VERSION 5.7 ;
  NOWIREEXTENSIONATPIN ON ;
  DIVIDERCHAR "/" ;
  BUSBITCHARS "[]" ;
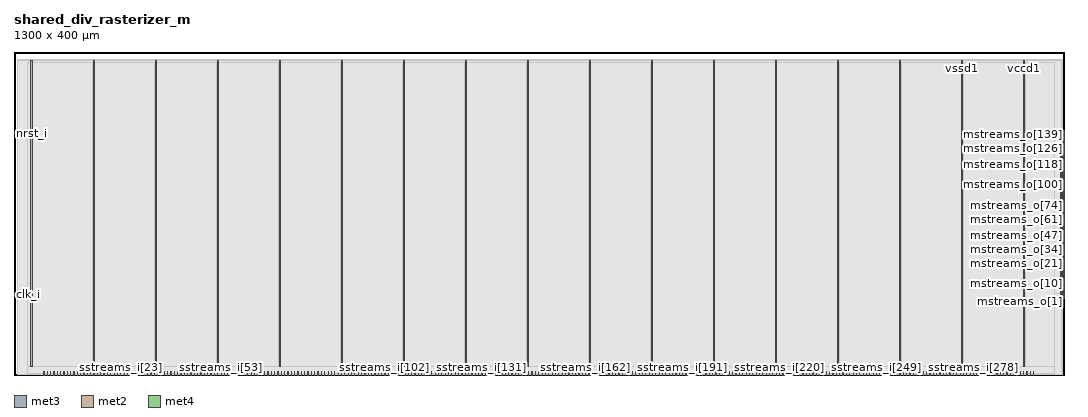
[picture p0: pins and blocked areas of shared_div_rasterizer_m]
MACRO shared_div_rasterizer_m
  CLASS BLOCK ;
  FOREIGN shared_div_rasterizer_m ;
  ORIGIN 0.000 0.000 ;
  SIZE 1300.000 BY 400.000 ;
  PIN clk_i
    DIRECTION INPUT ;
    USE SIGNAL ;
    ANTENNAGATEAREA 0.852000 ;
    ANTENNADIFFAREA 0.434700 ;
    PORT
      LAYER met3 ;
        RECT 0.000 99.320 4.000 99.920 ;
    END
  END clk_i
  PIN mstreams_i[0]
    DIRECTION INPUT ;
    USE SIGNAL ;
    ANTENNAGATEAREA 0.213000 ;
    PORT
      LAYER met3 ;
        RECT 1296.000 95.240 1300.000 95.840 ;
    END
  END mstreams_i[0]
  PIN mstreams_i[1]
    DIRECTION INPUT ;
    USE SIGNAL ;
    ANTENNAGATEAREA 0.159000 ;
    PORT
      LAYER met3 ;
        RECT 1296.000 96.600 1300.000 97.200 ;
    END
  END mstreams_i[1]
  PIN mstreams_i[2]
    DIRECTION INPUT ;
    USE SIGNAL ;
    ANTENNAGATEAREA 0.247500 ;
    PORT
      LAYER met3 ;
        RECT 1296.000 97.960 1300.000 98.560 ;
    END
  END mstreams_i[2]
  PIN mstreams_o[0]
    DIRECTION OUTPUT TRISTATE ;
    USE SIGNAL ;
    ANTENNADIFFAREA 2.673000 ;
    PORT
      LAYER met3 ;
        RECT 1296.000 99.320 1300.000 99.920 ;
    END
  END mstreams_o[0]
  PIN mstreams_o[100]
    DIRECTION OUTPUT TRISTATE ;
    USE SIGNAL ;
    ANTENNADIFFAREA 2.673000 ;
    PORT
      LAYER met3 ;
        RECT 1296.000 235.320 1300.000 235.920 ;
    END
  END mstreams_o[100]
  PIN mstreams_o[101]
    DIRECTION OUTPUT TRISTATE ;
    USE SIGNAL ;
    ANTENNADIFFAREA 2.673000 ;
    PORT
      LAYER met3 ;
        RECT 1296.000 236.680 1300.000 237.280 ;
    END
  END mstreams_o[101]
  PIN mstreams_o[102]
    DIRECTION OUTPUT TRISTATE ;
    USE SIGNAL ;
    ANTENNADIFFAREA 2.673000 ;
    PORT
      LAYER met3 ;
        RECT 1296.000 238.040 1300.000 238.640 ;
    END
  END mstreams_o[102]
  PIN mstreams_o[103]
    DIRECTION OUTPUT TRISTATE ;
    USE SIGNAL ;
    ANTENNADIFFAREA 2.673000 ;
    PORT
      LAYER met3 ;
        RECT 1296.000 239.400 1300.000 240.000 ;
    END
  END mstreams_o[103]
  PIN mstreams_o[104]
    DIRECTION OUTPUT TRISTATE ;
    USE SIGNAL ;
    ANTENNADIFFAREA 2.673000 ;
    PORT
      LAYER met3 ;
        RECT 1296.000 240.760 1300.000 241.360 ;
    END
  END mstreams_o[104]
  PIN mstreams_o[105]
    DIRECTION OUTPUT TRISTATE ;
    USE SIGNAL ;
    ANTENNADIFFAREA 2.673000 ;
    PORT
      LAYER met3 ;
        RECT 1296.000 242.120 1300.000 242.720 ;
    END
  END mstreams_o[105]
  PIN mstreams_o[106]
    DIRECTION OUTPUT TRISTATE ;
    USE SIGNAL ;
    ANTENNADIFFAREA 2.673000 ;
    PORT
      LAYER met3 ;
        RECT 1296.000 243.480 1300.000 244.080 ;
    END
  END mstreams_o[106]
  PIN mstreams_o[107]
    DIRECTION OUTPUT TRISTATE ;
    USE SIGNAL ;
    ANTENNADIFFAREA 2.673000 ;
    PORT
      LAYER met3 ;
        RECT 1296.000 244.840 1300.000 245.440 ;
    END
  END mstreams_o[107]
  PIN mstreams_o[108]
    DIRECTION OUTPUT TRISTATE ;
    USE SIGNAL ;
    ANTENNADIFFAREA 2.673000 ;
    PORT
      LAYER met3 ;
        RECT 1296.000 246.200 1300.000 246.800 ;
    END
  END mstreams_o[108]
  PIN mstreams_o[109]
    DIRECTION OUTPUT TRISTATE ;
    USE SIGNAL ;
    ANTENNADIFFAREA 2.673000 ;
    PORT
      LAYER met3 ;
        RECT 1296.000 247.560 1300.000 248.160 ;
    END
  END mstreams_o[109]
  PIN mstreams_o[10]
    DIRECTION OUTPUT TRISTATE ;
    USE SIGNAL ;
    ANTENNADIFFAREA 2.673000 ;
    PORT
      LAYER met3 ;
        RECT 1296.000 112.920 1300.000 113.520 ;
    END
  END mstreams_o[10]
  PIN mstreams_o[110]
    DIRECTION OUTPUT TRISTATE ;
    USE SIGNAL ;
    ANTENNADIFFAREA 2.673000 ;
    PORT
      LAYER met3 ;
        RECT 1296.000 248.920 1300.000 249.520 ;
    END
  END mstreams_o[110]
  PIN mstreams_o[111]
    DIRECTION OUTPUT TRISTATE ;
    USE SIGNAL ;
    ANTENNADIFFAREA 2.673000 ;
    PORT
      LAYER met3 ;
        RECT 1296.000 250.280 1300.000 250.880 ;
    END
  END mstreams_o[111]
  PIN mstreams_o[112]
    DIRECTION OUTPUT TRISTATE ;
    USE SIGNAL ;
    ANTENNADIFFAREA 2.673000 ;
    PORT
      LAYER met3 ;
        RECT 1296.000 251.640 1300.000 252.240 ;
    END
  END mstreams_o[112]
  PIN mstreams_o[113]
    DIRECTION OUTPUT TRISTATE ;
    USE SIGNAL ;
    ANTENNADIFFAREA 2.673000 ;
    PORT
      LAYER met3 ;
        RECT 1296.000 253.000 1300.000 253.600 ;
    END
  END mstreams_o[113]
  PIN mstreams_o[114]
    DIRECTION OUTPUT TRISTATE ;
    USE SIGNAL ;
    ANTENNADIFFAREA 2.673000 ;
    PORT
      LAYER met3 ;
        RECT 1296.000 254.360 1300.000 254.960 ;
    END
  END mstreams_o[114]
  PIN mstreams_o[115]
    DIRECTION OUTPUT TRISTATE ;
    USE SIGNAL ;
    ANTENNADIFFAREA 2.673000 ;
    PORT
      LAYER met3 ;
        RECT 1296.000 255.720 1300.000 256.320 ;
    END
  END mstreams_o[115]
  PIN mstreams_o[116]
    DIRECTION OUTPUT TRISTATE ;
    USE SIGNAL ;
    ANTENNADIFFAREA 2.673000 ;
    PORT
      LAYER met3 ;
        RECT 1296.000 257.080 1300.000 257.680 ;
    END
  END mstreams_o[116]
  PIN mstreams_o[117]
    DIRECTION OUTPUT TRISTATE ;
    USE SIGNAL ;
    ANTENNADIFFAREA 2.673000 ;
    PORT
      LAYER met3 ;
        RECT 1296.000 258.440 1300.000 259.040 ;
    END
  END mstreams_o[117]
  PIN mstreams_o[118]
    DIRECTION OUTPUT TRISTATE ;
    USE SIGNAL ;
    ANTENNADIFFAREA 2.673000 ;
    PORT
      LAYER met3 ;
        RECT 1296.000 259.800 1300.000 260.400 ;
    END
  END mstreams_o[118]
  PIN mstreams_o[119]
    DIRECTION OUTPUT TRISTATE ;
    USE SIGNAL ;
    ANTENNADIFFAREA 2.673000 ;
    PORT
      LAYER met3 ;
        RECT 1296.000 261.160 1300.000 261.760 ;
    END
  END mstreams_o[119]
  PIN mstreams_o[11]
    DIRECTION OUTPUT TRISTATE ;
    USE SIGNAL ;
    ANTENNADIFFAREA 2.673000 ;
    PORT
      LAYER met3 ;
        RECT 1296.000 114.280 1300.000 114.880 ;
    END
  END mstreams_o[11]
  PIN mstreams_o[120]
    DIRECTION OUTPUT TRISTATE ;
    USE SIGNAL ;
    ANTENNADIFFAREA 2.673000 ;
    PORT
      LAYER met3 ;
        RECT 1296.000 262.520 1300.000 263.120 ;
    END
  END mstreams_o[120]
  PIN mstreams_o[121]
    DIRECTION OUTPUT TRISTATE ;
    USE SIGNAL ;
    ANTENNADIFFAREA 2.673000 ;
    PORT
      LAYER met3 ;
        RECT 1296.000 263.880 1300.000 264.480 ;
    END
  END mstreams_o[121]
  PIN mstreams_o[122]
    DIRECTION OUTPUT TRISTATE ;
    USE SIGNAL ;
    ANTENNADIFFAREA 2.673000 ;
    PORT
      LAYER met3 ;
        RECT 1296.000 265.240 1300.000 265.840 ;
    END
  END mstreams_o[122]
  PIN mstreams_o[123]
    DIRECTION OUTPUT TRISTATE ;
    USE SIGNAL ;
    ANTENNADIFFAREA 2.673000 ;
    PORT
      LAYER met3 ;
        RECT 1296.000 266.600 1300.000 267.200 ;
    END
  END mstreams_o[123]
  PIN mstreams_o[124]
    DIRECTION OUTPUT TRISTATE ;
    USE SIGNAL ;
    ANTENNADIFFAREA 2.673000 ;
    PORT
      LAYER met3 ;
        RECT 1296.000 267.960 1300.000 268.560 ;
    END
  END mstreams_o[124]
  PIN mstreams_o[125]
    DIRECTION OUTPUT TRISTATE ;
    USE SIGNAL ;
    ANTENNADIFFAREA 2.673000 ;
    PORT
      LAYER met3 ;
        RECT 1296.000 269.320 1300.000 269.920 ;
    END
  END mstreams_o[125]
  PIN mstreams_o[126]
    DIRECTION OUTPUT TRISTATE ;
    USE SIGNAL ;
    ANTENNADIFFAREA 2.673000 ;
    PORT
      LAYER met3 ;
        RECT 1296.000 270.680 1300.000 271.280 ;
    END
  END mstreams_o[126]
  PIN mstreams_o[127]
    DIRECTION OUTPUT TRISTATE ;
    USE SIGNAL ;
    ANTENNADIFFAREA 2.673000 ;
    PORT
      LAYER met3 ;
        RECT 1296.000 272.040 1300.000 272.640 ;
    END
  END mstreams_o[127]
  PIN mstreams_o[128]
    DIRECTION OUTPUT TRISTATE ;
    USE SIGNAL ;
    ANTENNADIFFAREA 2.673000 ;
    PORT
      LAYER met3 ;
        RECT 1296.000 273.400 1300.000 274.000 ;
    END
  END mstreams_o[128]
  PIN mstreams_o[129]
    DIRECTION OUTPUT TRISTATE ;
    USE SIGNAL ;
    ANTENNADIFFAREA 2.673000 ;
    PORT
      LAYER met3 ;
        RECT 1296.000 274.760 1300.000 275.360 ;
    END
  END mstreams_o[129]
  PIN mstreams_o[12]
    DIRECTION OUTPUT TRISTATE ;
    USE SIGNAL ;
    ANTENNADIFFAREA 2.673000 ;
    PORT
      LAYER met3 ;
        RECT 1296.000 115.640 1300.000 116.240 ;
    END
  END mstreams_o[12]
  PIN mstreams_o[130]
    DIRECTION OUTPUT TRISTATE ;
    USE SIGNAL ;
    ANTENNADIFFAREA 2.673000 ;
    PORT
      LAYER met3 ;
        RECT 1296.000 276.120 1300.000 276.720 ;
    END
  END mstreams_o[130]
  PIN mstreams_o[131]
    DIRECTION OUTPUT TRISTATE ;
    USE SIGNAL ;
    ANTENNADIFFAREA 2.673000 ;
    PORT
      LAYER met3 ;
        RECT 1296.000 277.480 1300.000 278.080 ;
    END
  END mstreams_o[131]
  PIN mstreams_o[132]
    DIRECTION OUTPUT TRISTATE ;
    USE SIGNAL ;
    ANTENNADIFFAREA 2.673000 ;
    PORT
      LAYER met3 ;
        RECT 1296.000 278.840 1300.000 279.440 ;
    END
  END mstreams_o[132]
  PIN mstreams_o[133]
    DIRECTION OUTPUT TRISTATE ;
    USE SIGNAL ;
    ANTENNADIFFAREA 2.673000 ;
    PORT
      LAYER met3 ;
        RECT 1296.000 280.200 1300.000 280.800 ;
    END
  END mstreams_o[133]
  PIN mstreams_o[134]
    DIRECTION OUTPUT TRISTATE ;
    USE SIGNAL ;
    ANTENNADIFFAREA 2.673000 ;
    PORT
      LAYER met3 ;
        RECT 1296.000 281.560 1300.000 282.160 ;
    END
  END mstreams_o[134]
  PIN mstreams_o[135]
    DIRECTION OUTPUT TRISTATE ;
    USE SIGNAL ;
    ANTENNADIFFAREA 2.673000 ;
    PORT
      LAYER met3 ;
        RECT 1296.000 282.920 1300.000 283.520 ;
    END
  END mstreams_o[135]
  PIN mstreams_o[136]
    DIRECTION OUTPUT TRISTATE ;
    USE SIGNAL ;
    ANTENNADIFFAREA 2.673000 ;
    PORT
      LAYER met3 ;
        RECT 1296.000 284.280 1300.000 284.880 ;
    END
  END mstreams_o[136]
  PIN mstreams_o[137]
    DIRECTION OUTPUT TRISTATE ;
    USE SIGNAL ;
    ANTENNADIFFAREA 2.673000 ;
    PORT
      LAYER met3 ;
        RECT 1296.000 285.640 1300.000 286.240 ;
    END
  END mstreams_o[137]
  PIN mstreams_o[138]
    DIRECTION OUTPUT TRISTATE ;
    USE SIGNAL ;
    ANTENNADIFFAREA 2.673000 ;
    PORT
      LAYER met3 ;
        RECT 1296.000 287.000 1300.000 287.600 ;
    END
  END mstreams_o[138]
  PIN mstreams_o[139]
    DIRECTION OUTPUT TRISTATE ;
    USE SIGNAL ;
    ANTENNADIFFAREA 2.673000 ;
    PORT
      LAYER met3 ;
        RECT 1296.000 288.360 1300.000 288.960 ;
    END
  END mstreams_o[139]
  PIN mstreams_o[13]
    DIRECTION OUTPUT TRISTATE ;
    USE SIGNAL ;
    ANTENNADIFFAREA 2.673000 ;
    PORT
      LAYER met3 ;
        RECT 1296.000 117.000 1300.000 117.600 ;
    END
  END mstreams_o[13]
  PIN mstreams_o[140]
    DIRECTION OUTPUT TRISTATE ;
    USE SIGNAL ;
    ANTENNADIFFAREA 2.673000 ;
    PORT
      LAYER met3 ;
        RECT 1296.000 289.720 1300.000 290.320 ;
    END
  END mstreams_o[140]
  PIN mstreams_o[141]
    DIRECTION OUTPUT TRISTATE ;
    USE SIGNAL ;
    ANTENNADIFFAREA 2.673000 ;
    PORT
      LAYER met3 ;
        RECT 1296.000 291.080 1300.000 291.680 ;
    END
  END mstreams_o[141]
  PIN mstreams_o[142]
    DIRECTION OUTPUT TRISTATE ;
    USE SIGNAL ;
    ANTENNADIFFAREA 2.673000 ;
    PORT
      LAYER met3 ;
        RECT 1296.000 292.440 1300.000 293.040 ;
    END
  END mstreams_o[142]
  PIN mstreams_o[143]
    DIRECTION OUTPUT TRISTATE ;
    USE SIGNAL ;
    ANTENNADIFFAREA 2.673000 ;
    PORT
      LAYER met3 ;
        RECT 1296.000 293.800 1300.000 294.400 ;
    END
  END mstreams_o[143]
  PIN mstreams_o[144]
    DIRECTION OUTPUT TRISTATE ;
    USE SIGNAL ;
    ANTENNADIFFAREA 2.673000 ;
    PORT
      LAYER met3 ;
        RECT 1296.000 295.160 1300.000 295.760 ;
    END
  END mstreams_o[144]
  PIN mstreams_o[145]
    DIRECTION OUTPUT TRISTATE ;
    USE SIGNAL ;
    ANTENNADIFFAREA 2.673000 ;
    PORT
      LAYER met3 ;
        RECT 1296.000 296.520 1300.000 297.120 ;
    END
  END mstreams_o[145]
  PIN mstreams_o[146]
    DIRECTION OUTPUT TRISTATE ;
    USE SIGNAL ;
    ANTENNADIFFAREA 2.673000 ;
    PORT
      LAYER met3 ;
        RECT 1296.000 297.880 1300.000 298.480 ;
    END
  END mstreams_o[146]
  PIN mstreams_o[147]
    DIRECTION OUTPUT TRISTATE ;
    USE SIGNAL ;
    ANTENNADIFFAREA 2.673000 ;
    PORT
      LAYER met3 ;
        RECT 1296.000 299.240 1300.000 299.840 ;
    END
  END mstreams_o[147]
  PIN mstreams_o[148]
    DIRECTION OUTPUT TRISTATE ;
    USE SIGNAL ;
    ANTENNADIFFAREA 2.673000 ;
    PORT
      LAYER met3 ;
        RECT 1296.000 300.600 1300.000 301.200 ;
    END
  END mstreams_o[148]
  PIN mstreams_o[149]
    DIRECTION OUTPUT TRISTATE ;
    USE SIGNAL ;
    PORT
      LAYER met3 ;
        RECT 1296.000 301.960 1300.000 302.560 ;
    END
  END mstreams_o[149]
  PIN mstreams_o[14]
    DIRECTION OUTPUT TRISTATE ;
    USE SIGNAL ;
    ANTENNADIFFAREA 2.673000 ;
    PORT
      LAYER met3 ;
        RECT 1296.000 118.360 1300.000 118.960 ;
    END
  END mstreams_o[14]
  PIN mstreams_o[15]
    DIRECTION OUTPUT TRISTATE ;
    USE SIGNAL ;
    ANTENNADIFFAREA 2.673000 ;
    PORT
      LAYER met3 ;
        RECT 1296.000 119.720 1300.000 120.320 ;
    END
  END mstreams_o[15]
  PIN mstreams_o[16]
    DIRECTION OUTPUT TRISTATE ;
    USE SIGNAL ;
    ANTENNADIFFAREA 2.673000 ;
    PORT
      LAYER met3 ;
        RECT 1296.000 121.080 1300.000 121.680 ;
    END
  END mstreams_o[16]
  PIN mstreams_o[17]
    DIRECTION OUTPUT TRISTATE ;
    USE SIGNAL ;
    ANTENNADIFFAREA 2.673000 ;
    PORT
      LAYER met3 ;
        RECT 1296.000 122.440 1300.000 123.040 ;
    END
  END mstreams_o[17]
  PIN mstreams_o[18]
    DIRECTION OUTPUT TRISTATE ;
    USE SIGNAL ;
    ANTENNADIFFAREA 2.673000 ;
    PORT
      LAYER met3 ;
        RECT 1296.000 123.800 1300.000 124.400 ;
    END
  END mstreams_o[18]
  PIN mstreams_o[19]
    DIRECTION OUTPUT TRISTATE ;
    USE SIGNAL ;
    ANTENNADIFFAREA 2.673000 ;
    PORT
      LAYER met3 ;
        RECT 1296.000 125.160 1300.000 125.760 ;
    END
  END mstreams_o[19]
  PIN mstreams_o[1]
    DIRECTION OUTPUT TRISTATE ;
    USE SIGNAL ;
    ANTENNADIFFAREA 2.673000 ;
    PORT
      LAYER met3 ;
        RECT 1296.000 100.680 1300.000 101.280 ;
    END
  END mstreams_o[1]
  PIN mstreams_o[20]
    DIRECTION OUTPUT TRISTATE ;
    USE SIGNAL ;
    ANTENNADIFFAREA 2.673000 ;
    PORT
      LAYER met3 ;
        RECT 1296.000 126.520 1300.000 127.120 ;
    END
  END mstreams_o[20]
  PIN mstreams_o[21]
    DIRECTION OUTPUT TRISTATE ;
    USE SIGNAL ;
    ANTENNADIFFAREA 2.673000 ;
    PORT
      LAYER met3 ;
        RECT 1296.000 127.880 1300.000 128.480 ;
    END
  END mstreams_o[21]
  PIN mstreams_o[22]
    DIRECTION OUTPUT TRISTATE ;
    USE SIGNAL ;
    ANTENNADIFFAREA 2.673000 ;
    PORT
      LAYER met3 ;
        RECT 1296.000 129.240 1300.000 129.840 ;
    END
  END mstreams_o[22]
  PIN mstreams_o[23]
    DIRECTION OUTPUT TRISTATE ;
    USE SIGNAL ;
    ANTENNADIFFAREA 2.673000 ;
    PORT
      LAYER met3 ;
        RECT 1296.000 130.600 1300.000 131.200 ;
    END
  END mstreams_o[23]
  PIN mstreams_o[24]
    DIRECTION OUTPUT TRISTATE ;
    USE SIGNAL ;
    ANTENNADIFFAREA 2.673000 ;
    PORT
      LAYER met3 ;
        RECT 1296.000 131.960 1300.000 132.560 ;
    END
  END mstreams_o[24]
  PIN mstreams_o[25]
    DIRECTION OUTPUT TRISTATE ;
    USE SIGNAL ;
    ANTENNADIFFAREA 2.673000 ;
    PORT
      LAYER met3 ;
        RECT 1296.000 133.320 1300.000 133.920 ;
    END
  END mstreams_o[25]
  PIN mstreams_o[26]
    DIRECTION OUTPUT TRISTATE ;
    USE SIGNAL ;
    ANTENNADIFFAREA 2.673000 ;
    PORT
      LAYER met3 ;
        RECT 1296.000 134.680 1300.000 135.280 ;
    END
  END mstreams_o[26]
  PIN mstreams_o[27]
    DIRECTION OUTPUT TRISTATE ;
    USE SIGNAL ;
    ANTENNADIFFAREA 2.673000 ;
    PORT
      LAYER met3 ;
        RECT 1296.000 136.040 1300.000 136.640 ;
    END
  END mstreams_o[27]
  PIN mstreams_o[28]
    DIRECTION OUTPUT TRISTATE ;
    USE SIGNAL ;
    ANTENNADIFFAREA 2.673000 ;
    PORT
      LAYER met3 ;
        RECT 1296.000 137.400 1300.000 138.000 ;
    END
  END mstreams_o[28]
  PIN mstreams_o[29]
    DIRECTION OUTPUT TRISTATE ;
    USE SIGNAL ;
    ANTENNADIFFAREA 2.673000 ;
    PORT
      LAYER met3 ;
        RECT 1296.000 138.760 1300.000 139.360 ;
    END
  END mstreams_o[29]
  PIN mstreams_o[2]
    DIRECTION OUTPUT TRISTATE ;
    USE SIGNAL ;
    ANTENNADIFFAREA 2.673000 ;
    PORT
      LAYER met3 ;
        RECT 1296.000 102.040 1300.000 102.640 ;
    END
  END mstreams_o[2]
  PIN mstreams_o[30]
    DIRECTION OUTPUT TRISTATE ;
    USE SIGNAL ;
    ANTENNADIFFAREA 2.673000 ;
    PORT
      LAYER met3 ;
        RECT 1296.000 140.120 1300.000 140.720 ;
    END
  END mstreams_o[30]
  PIN mstreams_o[31]
    DIRECTION OUTPUT TRISTATE ;
    USE SIGNAL ;
    ANTENNADIFFAREA 2.673000 ;
    PORT
      LAYER met3 ;
        RECT 1296.000 141.480 1300.000 142.080 ;
    END
  END mstreams_o[31]
  PIN mstreams_o[32]
    DIRECTION OUTPUT TRISTATE ;
    USE SIGNAL ;
    ANTENNADIFFAREA 2.673000 ;
    PORT
      LAYER met3 ;
        RECT 1296.000 142.840 1300.000 143.440 ;
    END
  END mstreams_o[32]
  PIN mstreams_o[33]
    DIRECTION OUTPUT TRISTATE ;
    USE SIGNAL ;
    ANTENNADIFFAREA 2.673000 ;
    PORT
      LAYER met3 ;
        RECT 1296.000 144.200 1300.000 144.800 ;
    END
  END mstreams_o[33]
  PIN mstreams_o[34]
    DIRECTION OUTPUT TRISTATE ;
    USE SIGNAL ;
    ANTENNADIFFAREA 2.673000 ;
    PORT
      LAYER met3 ;
        RECT 1296.000 145.560 1300.000 146.160 ;
    END
  END mstreams_o[34]
  PIN mstreams_o[35]
    DIRECTION OUTPUT TRISTATE ;
    USE SIGNAL ;
    ANTENNADIFFAREA 2.673000 ;
    PORT
      LAYER met3 ;
        RECT 1296.000 146.920 1300.000 147.520 ;
    END
  END mstreams_o[35]
  PIN mstreams_o[36]
    DIRECTION OUTPUT TRISTATE ;
    USE SIGNAL ;
    ANTENNADIFFAREA 2.673000 ;
    PORT
      LAYER met3 ;
        RECT 1296.000 148.280 1300.000 148.880 ;
    END
  END mstreams_o[36]
  PIN mstreams_o[37]
    DIRECTION OUTPUT TRISTATE ;
    USE SIGNAL ;
    ANTENNADIFFAREA 2.673000 ;
    PORT
      LAYER met3 ;
        RECT 1296.000 149.640 1300.000 150.240 ;
    END
  END mstreams_o[37]
  PIN mstreams_o[38]
    DIRECTION OUTPUT TRISTATE ;
    USE SIGNAL ;
    ANTENNADIFFAREA 2.673000 ;
    PORT
      LAYER met3 ;
        RECT 1296.000 151.000 1300.000 151.600 ;
    END
  END mstreams_o[38]
  PIN mstreams_o[39]
    DIRECTION OUTPUT TRISTATE ;
    USE SIGNAL ;
    ANTENNADIFFAREA 2.673000 ;
    PORT
      LAYER met3 ;
        RECT 1296.000 152.360 1300.000 152.960 ;
    END
  END mstreams_o[39]
  PIN mstreams_o[3]
    DIRECTION OUTPUT TRISTATE ;
    USE SIGNAL ;
    ANTENNADIFFAREA 2.673000 ;
    PORT
      LAYER met3 ;
        RECT 1296.000 103.400 1300.000 104.000 ;
    END
  END mstreams_o[3]
  PIN mstreams_o[40]
    DIRECTION OUTPUT TRISTATE ;
    USE SIGNAL ;
    ANTENNADIFFAREA 2.673000 ;
    PORT
      LAYER met3 ;
        RECT 1296.000 153.720 1300.000 154.320 ;
    END
  END mstreams_o[40]
  PIN mstreams_o[41]
    DIRECTION OUTPUT TRISTATE ;
    USE SIGNAL ;
    ANTENNADIFFAREA 2.673000 ;
    PORT
      LAYER met3 ;
        RECT 1296.000 155.080 1300.000 155.680 ;
    END
  END mstreams_o[41]
  PIN mstreams_o[42]
    DIRECTION OUTPUT TRISTATE ;
    USE SIGNAL ;
    ANTENNADIFFAREA 2.673000 ;
    PORT
      LAYER met3 ;
        RECT 1296.000 156.440 1300.000 157.040 ;
    END
  END mstreams_o[42]
  PIN mstreams_o[43]
    DIRECTION OUTPUT TRISTATE ;
    USE SIGNAL ;
    ANTENNADIFFAREA 2.673000 ;
    PORT
      LAYER met3 ;
        RECT 1296.000 157.800 1300.000 158.400 ;
    END
  END mstreams_o[43]
  PIN mstreams_o[44]
    DIRECTION OUTPUT TRISTATE ;
    USE SIGNAL ;
    ANTENNADIFFAREA 2.673000 ;
    PORT
      LAYER met3 ;
        RECT 1296.000 159.160 1300.000 159.760 ;
    END
  END mstreams_o[44]
  PIN mstreams_o[45]
    DIRECTION OUTPUT TRISTATE ;
    USE SIGNAL ;
    ANTENNADIFFAREA 2.673000 ;
    PORT
      LAYER met3 ;
        RECT 1296.000 160.520 1300.000 161.120 ;
    END
  END mstreams_o[45]
  PIN mstreams_o[46]
    DIRECTION OUTPUT TRISTATE ;
    USE SIGNAL ;
    ANTENNADIFFAREA 2.673000 ;
    PORT
      LAYER met3 ;
        RECT 1296.000 161.880 1300.000 162.480 ;
    END
  END mstreams_o[46]
  PIN mstreams_o[47]
    DIRECTION OUTPUT TRISTATE ;
    USE SIGNAL ;
    ANTENNADIFFAREA 2.673000 ;
    PORT
      LAYER met3 ;
        RECT 1296.000 163.240 1300.000 163.840 ;
    END
  END mstreams_o[47]
  PIN mstreams_o[48]
    DIRECTION OUTPUT TRISTATE ;
    USE SIGNAL ;
    ANTENNADIFFAREA 2.673000 ;
    PORT
      LAYER met3 ;
        RECT 1296.000 164.600 1300.000 165.200 ;
    END
  END mstreams_o[48]
  PIN mstreams_o[49]
    DIRECTION OUTPUT TRISTATE ;
    USE SIGNAL ;
    PORT
      LAYER met3 ;
        RECT 1296.000 165.960 1300.000 166.560 ;
    END
  END mstreams_o[49]
  PIN mstreams_o[4]
    DIRECTION OUTPUT TRISTATE ;
    USE SIGNAL ;
    ANTENNADIFFAREA 2.673000 ;
    PORT
      LAYER met3 ;
        RECT 1296.000 104.760 1300.000 105.360 ;
    END
  END mstreams_o[4]
  PIN mstreams_o[50]
    DIRECTION OUTPUT TRISTATE ;
    USE SIGNAL ;
    ANTENNADIFFAREA 2.673000 ;
    PORT
      LAYER met3 ;
        RECT 1296.000 167.320 1300.000 167.920 ;
    END
  END mstreams_o[50]
  PIN mstreams_o[51]
    DIRECTION OUTPUT TRISTATE ;
    USE SIGNAL ;
    ANTENNADIFFAREA 2.673000 ;
    PORT
      LAYER met3 ;
        RECT 1296.000 168.680 1300.000 169.280 ;
    END
  END mstreams_o[51]
  PIN mstreams_o[52]
    DIRECTION OUTPUT TRISTATE ;
    USE SIGNAL ;
    ANTENNADIFFAREA 2.673000 ;
    PORT
      LAYER met3 ;
        RECT 1296.000 170.040 1300.000 170.640 ;
    END
  END mstreams_o[52]
  PIN mstreams_o[53]
    DIRECTION OUTPUT TRISTATE ;
    USE SIGNAL ;
    ANTENNADIFFAREA 2.673000 ;
    PORT
      LAYER met3 ;
        RECT 1296.000 171.400 1300.000 172.000 ;
    END
  END mstreams_o[53]
  PIN mstreams_o[54]
    DIRECTION OUTPUT TRISTATE ;
    USE SIGNAL ;
    ANTENNADIFFAREA 2.673000 ;
    PORT
      LAYER met3 ;
        RECT 1296.000 172.760 1300.000 173.360 ;
    END
  END mstreams_o[54]
  PIN mstreams_o[55]
    DIRECTION OUTPUT TRISTATE ;
    USE SIGNAL ;
    ANTENNADIFFAREA 2.673000 ;
    PORT
      LAYER met3 ;
        RECT 1296.000 174.120 1300.000 174.720 ;
    END
  END mstreams_o[55]
  PIN mstreams_o[56]
    DIRECTION OUTPUT TRISTATE ;
    USE SIGNAL ;
    ANTENNADIFFAREA 2.673000 ;
    PORT
      LAYER met3 ;
        RECT 1296.000 175.480 1300.000 176.080 ;
    END
  END mstreams_o[56]
  PIN mstreams_o[57]
    DIRECTION OUTPUT TRISTATE ;
    USE SIGNAL ;
    ANTENNADIFFAREA 2.673000 ;
    PORT
      LAYER met3 ;
        RECT 1296.000 176.840 1300.000 177.440 ;
    END
  END mstreams_o[57]
  PIN mstreams_o[58]
    DIRECTION OUTPUT TRISTATE ;
    USE SIGNAL ;
    ANTENNADIFFAREA 2.673000 ;
    PORT
      LAYER met3 ;
        RECT 1296.000 178.200 1300.000 178.800 ;
    END
  END mstreams_o[58]
  PIN mstreams_o[59]
    DIRECTION OUTPUT TRISTATE ;
    USE SIGNAL ;
    ANTENNADIFFAREA 2.673000 ;
    PORT
      LAYER met3 ;
        RECT 1296.000 179.560 1300.000 180.160 ;
    END
  END mstreams_o[59]
  PIN mstreams_o[5]
    DIRECTION OUTPUT TRISTATE ;
    USE SIGNAL ;
    ANTENNADIFFAREA 2.673000 ;
    PORT
      LAYER met3 ;
        RECT 1296.000 106.120 1300.000 106.720 ;
    END
  END mstreams_o[5]
  PIN mstreams_o[60]
    DIRECTION OUTPUT TRISTATE ;
    USE SIGNAL ;
    ANTENNADIFFAREA 2.673000 ;
    PORT
      LAYER met3 ;
        RECT 1296.000 180.920 1300.000 181.520 ;
    END
  END mstreams_o[60]
  PIN mstreams_o[61]
    DIRECTION OUTPUT TRISTATE ;
    USE SIGNAL ;
    ANTENNADIFFAREA 2.673000 ;
    PORT
      LAYER met3 ;
        RECT 1296.000 182.280 1300.000 182.880 ;
    END
  END mstreams_o[61]
  PIN mstreams_o[62]
    DIRECTION OUTPUT TRISTATE ;
    USE SIGNAL ;
    ANTENNADIFFAREA 2.673000 ;
    PORT
      LAYER met3 ;
        RECT 1296.000 183.640 1300.000 184.240 ;
    END
  END mstreams_o[62]
  PIN mstreams_o[63]
    DIRECTION OUTPUT TRISTATE ;
    USE SIGNAL ;
    ANTENNADIFFAREA 2.673000 ;
    PORT
      LAYER met3 ;
        RECT 1296.000 185.000 1300.000 185.600 ;
    END
  END mstreams_o[63]
  PIN mstreams_o[64]
    DIRECTION OUTPUT TRISTATE ;
    USE SIGNAL ;
    ANTENNADIFFAREA 2.673000 ;
    PORT
      LAYER met3 ;
        RECT 1296.000 186.360 1300.000 186.960 ;
    END
  END mstreams_o[64]
  PIN mstreams_o[65]
    DIRECTION OUTPUT TRISTATE ;
    USE SIGNAL ;
    ANTENNADIFFAREA 2.673000 ;
    PORT
      LAYER met3 ;
        RECT 1296.000 187.720 1300.000 188.320 ;
    END
  END mstreams_o[65]
  PIN mstreams_o[66]
    DIRECTION OUTPUT TRISTATE ;
    USE SIGNAL ;
    ANTENNADIFFAREA 2.673000 ;
    PORT
      LAYER met3 ;
        RECT 1296.000 189.080 1300.000 189.680 ;
    END
  END mstreams_o[66]
  PIN mstreams_o[67]
    DIRECTION OUTPUT TRISTATE ;
    USE SIGNAL ;
    ANTENNADIFFAREA 2.673000 ;
    PORT
      LAYER met3 ;
        RECT 1296.000 190.440 1300.000 191.040 ;
    END
  END mstreams_o[67]
  PIN mstreams_o[68]
    DIRECTION OUTPUT TRISTATE ;
    USE SIGNAL ;
    ANTENNADIFFAREA 2.673000 ;
    PORT
      LAYER met3 ;
        RECT 1296.000 191.800 1300.000 192.400 ;
    END
  END mstreams_o[68]
  PIN mstreams_o[69]
    DIRECTION OUTPUT TRISTATE ;
    USE SIGNAL ;
    ANTENNADIFFAREA 2.673000 ;
    PORT
      LAYER met3 ;
        RECT 1296.000 193.160 1300.000 193.760 ;
    END
  END mstreams_o[69]
  PIN mstreams_o[6]
    DIRECTION OUTPUT TRISTATE ;
    USE SIGNAL ;
    ANTENNADIFFAREA 2.673000 ;
    PORT
      LAYER met3 ;
        RECT 1296.000 107.480 1300.000 108.080 ;
    END
  END mstreams_o[6]
  PIN mstreams_o[70]
    DIRECTION OUTPUT TRISTATE ;
    USE SIGNAL ;
    ANTENNADIFFAREA 2.673000 ;
    PORT
      LAYER met3 ;
        RECT 1296.000 194.520 1300.000 195.120 ;
    END
  END mstreams_o[70]
  PIN mstreams_o[71]
    DIRECTION OUTPUT TRISTATE ;
    USE SIGNAL ;
    ANTENNADIFFAREA 2.673000 ;
    PORT
      LAYER met3 ;
        RECT 1296.000 195.880 1300.000 196.480 ;
    END
  END mstreams_o[71]
  PIN mstreams_o[72]
    DIRECTION OUTPUT TRISTATE ;
    USE SIGNAL ;
    ANTENNADIFFAREA 2.673000 ;
    PORT
      LAYER met3 ;
        RECT 1296.000 197.240 1300.000 197.840 ;
    END
  END mstreams_o[72]
  PIN mstreams_o[73]
    DIRECTION OUTPUT TRISTATE ;
    USE SIGNAL ;
    ANTENNADIFFAREA 2.673000 ;
    PORT
      LAYER met3 ;
        RECT 1296.000 198.600 1300.000 199.200 ;
    END
  END mstreams_o[73]
  PIN mstreams_o[74]
    DIRECTION OUTPUT TRISTATE ;
    USE SIGNAL ;
    ANTENNADIFFAREA 2.673000 ;
    PORT
      LAYER met3 ;
        RECT 1296.000 199.960 1300.000 200.560 ;
    END
  END mstreams_o[74]
  PIN mstreams_o[75]
    DIRECTION OUTPUT TRISTATE ;
    USE SIGNAL ;
    ANTENNADIFFAREA 2.673000 ;
    PORT
      LAYER met3 ;
        RECT 1296.000 201.320 1300.000 201.920 ;
    END
  END mstreams_o[75]
  PIN mstreams_o[76]
    DIRECTION OUTPUT TRISTATE ;
    USE SIGNAL ;
    ANTENNADIFFAREA 2.673000 ;
    PORT
      LAYER met3 ;
        RECT 1296.000 202.680 1300.000 203.280 ;
    END
  END mstreams_o[76]
  PIN mstreams_o[77]
    DIRECTION OUTPUT TRISTATE ;
    USE SIGNAL ;
    ANTENNADIFFAREA 2.673000 ;
    PORT
      LAYER met3 ;
        RECT 1296.000 204.040 1300.000 204.640 ;
    END
  END mstreams_o[77]
  PIN mstreams_o[78]
    DIRECTION OUTPUT TRISTATE ;
    USE SIGNAL ;
    ANTENNADIFFAREA 2.673000 ;
    PORT
      LAYER met3 ;
        RECT 1296.000 205.400 1300.000 206.000 ;
    END
  END mstreams_o[78]
  PIN mstreams_o[79]
    DIRECTION OUTPUT TRISTATE ;
    USE SIGNAL ;
    ANTENNADIFFAREA 2.673000 ;
    PORT
      LAYER met3 ;
        RECT 1296.000 206.760 1300.000 207.360 ;
    END
  END mstreams_o[79]
  PIN mstreams_o[7]
    DIRECTION OUTPUT TRISTATE ;
    USE SIGNAL ;
    ANTENNADIFFAREA 2.673000 ;
    PORT
      LAYER met3 ;
        RECT 1296.000 108.840 1300.000 109.440 ;
    END
  END mstreams_o[7]
  PIN mstreams_o[80]
    DIRECTION OUTPUT TRISTATE ;
    USE SIGNAL ;
    ANTENNADIFFAREA 2.673000 ;
    PORT
      LAYER met3 ;
        RECT 1296.000 208.120 1300.000 208.720 ;
    END
  END mstreams_o[80]
  PIN mstreams_o[81]
    DIRECTION OUTPUT TRISTATE ;
    USE SIGNAL ;
    ANTENNADIFFAREA 2.673000 ;
    PORT
      LAYER met3 ;
        RECT 1296.000 209.480 1300.000 210.080 ;
    END
  END mstreams_o[81]
  PIN mstreams_o[82]
    DIRECTION OUTPUT TRISTATE ;
    USE SIGNAL ;
    ANTENNADIFFAREA 2.673000 ;
    PORT
      LAYER met3 ;
        RECT 1296.000 210.840 1300.000 211.440 ;
    END
  END mstreams_o[82]
  PIN mstreams_o[83]
    DIRECTION OUTPUT TRISTATE ;
    USE SIGNAL ;
    ANTENNADIFFAREA 2.673000 ;
    PORT
      LAYER met3 ;
        RECT 1296.000 212.200 1300.000 212.800 ;
    END
  END mstreams_o[83]
  PIN mstreams_o[84]
    DIRECTION OUTPUT TRISTATE ;
    USE SIGNAL ;
    ANTENNADIFFAREA 2.673000 ;
    PORT
      LAYER met3 ;
        RECT 1296.000 213.560 1300.000 214.160 ;
    END
  END mstreams_o[84]
  PIN mstreams_o[85]
    DIRECTION OUTPUT TRISTATE ;
    USE SIGNAL ;
    ANTENNADIFFAREA 2.673000 ;
    PORT
      LAYER met3 ;
        RECT 1296.000 214.920 1300.000 215.520 ;
    END
  END mstreams_o[85]
  PIN mstreams_o[86]
    DIRECTION OUTPUT TRISTATE ;
    USE SIGNAL ;
    ANTENNADIFFAREA 2.673000 ;
    PORT
      LAYER met3 ;
        RECT 1296.000 216.280 1300.000 216.880 ;
    END
  END mstreams_o[86]
  PIN mstreams_o[87]
    DIRECTION OUTPUT TRISTATE ;
    USE SIGNAL ;
    ANTENNADIFFAREA 2.673000 ;
    PORT
      LAYER met3 ;
        RECT 1296.000 217.640 1300.000 218.240 ;
    END
  END mstreams_o[87]
  PIN mstreams_o[88]
    DIRECTION OUTPUT TRISTATE ;
    USE SIGNAL ;
    ANTENNADIFFAREA 2.673000 ;
    PORT
      LAYER met3 ;
        RECT 1296.000 219.000 1300.000 219.600 ;
    END
  END mstreams_o[88]
  PIN mstreams_o[89]
    DIRECTION OUTPUT TRISTATE ;
    USE SIGNAL ;
    ANTENNADIFFAREA 2.673000 ;
    PORT
      LAYER met3 ;
        RECT 1296.000 220.360 1300.000 220.960 ;
    END
  END mstreams_o[89]
  PIN mstreams_o[8]
    DIRECTION OUTPUT TRISTATE ;
    USE SIGNAL ;
    ANTENNADIFFAREA 2.673000 ;
    PORT
      LAYER met3 ;
        RECT 1296.000 110.200 1300.000 110.800 ;
    END
  END mstreams_o[8]
  PIN mstreams_o[90]
    DIRECTION OUTPUT TRISTATE ;
    USE SIGNAL ;
    ANTENNADIFFAREA 2.673000 ;
    PORT
      LAYER met3 ;
        RECT 1296.000 221.720 1300.000 222.320 ;
    END
  END mstreams_o[90]
  PIN mstreams_o[91]
    DIRECTION OUTPUT TRISTATE ;
    USE SIGNAL ;
    ANTENNADIFFAREA 2.673000 ;
    PORT
      LAYER met3 ;
        RECT 1296.000 223.080 1300.000 223.680 ;
    END
  END mstreams_o[91]
  PIN mstreams_o[92]
    DIRECTION OUTPUT TRISTATE ;
    USE SIGNAL ;
    ANTENNADIFFAREA 2.673000 ;
    PORT
      LAYER met3 ;
        RECT 1296.000 224.440 1300.000 225.040 ;
    END
  END mstreams_o[92]
  PIN mstreams_o[93]
    DIRECTION OUTPUT TRISTATE ;
    USE SIGNAL ;
    ANTENNADIFFAREA 2.673000 ;
    PORT
      LAYER met3 ;
        RECT 1296.000 225.800 1300.000 226.400 ;
    END
  END mstreams_o[93]
  PIN mstreams_o[94]
    DIRECTION OUTPUT TRISTATE ;
    USE SIGNAL ;
    ANTENNADIFFAREA 2.673000 ;
    PORT
      LAYER met3 ;
        RECT 1296.000 227.160 1300.000 227.760 ;
    END
  END mstreams_o[94]
  PIN mstreams_o[95]
    DIRECTION OUTPUT TRISTATE ;
    USE SIGNAL ;
    ANTENNADIFFAREA 2.673000 ;
    PORT
      LAYER met3 ;
        RECT 1296.000 228.520 1300.000 229.120 ;
    END
  END mstreams_o[95]
  PIN mstreams_o[96]
    DIRECTION OUTPUT TRISTATE ;
    USE SIGNAL ;
    ANTENNADIFFAREA 2.673000 ;
    PORT
      LAYER met3 ;
        RECT 1296.000 229.880 1300.000 230.480 ;
    END
  END mstreams_o[96]
  PIN mstreams_o[97]
    DIRECTION OUTPUT TRISTATE ;
    USE SIGNAL ;
    ANTENNADIFFAREA 2.673000 ;
    PORT
      LAYER met3 ;
        RECT 1296.000 231.240 1300.000 231.840 ;
    END
  END mstreams_o[97]
  PIN mstreams_o[98]
    DIRECTION OUTPUT TRISTATE ;
    USE SIGNAL ;
    ANTENNADIFFAREA 2.673000 ;
    PORT
      LAYER met3 ;
        RECT 1296.000 232.600 1300.000 233.200 ;
    END
  END mstreams_o[98]
  PIN mstreams_o[99]
    DIRECTION OUTPUT TRISTATE ;
    USE SIGNAL ;
    PORT
      LAYER met3 ;
        RECT 1296.000 233.960 1300.000 234.560 ;
    END
  END mstreams_o[99]
  PIN mstreams_o[9]
    DIRECTION OUTPUT TRISTATE ;
    USE SIGNAL ;
    ANTENNADIFFAREA 2.673000 ;
    PORT
      LAYER met3 ;
        RECT 1296.000 111.560 1300.000 112.160 ;
    END
  END mstreams_o[9]
  PIN nrst_i
    DIRECTION INPUT ;
    USE SIGNAL ;
    ANTENNAGATEAREA 0.990000 ;
    PORT
      LAYER met3 ;
        RECT 0.000 299.240 4.000 299.840 ;
    END
  END nrst_i
  PIN sstreams_i[0]
    DIRECTION INPUT ;
    USE SIGNAL ;
    ANTENNAGATEAREA 0.159000 ;
    PORT
      LAYER met2 ;
        RECT 36.890 0.000 37.170 4.000 ;
    END
  END sstreams_i[0]
  PIN sstreams_i[100]
    DIRECTION INPUT ;
    USE SIGNAL ;
    ANTENNAGATEAREA 0.196500 ;
    PORT
      LAYER met2 ;
        RECT 450.890 0.000 451.170 4.000 ;
    END
  END sstreams_i[100]
  PIN sstreams_i[101]
    DIRECTION INPUT ;
    USE SIGNAL ;
    ANTENNAGATEAREA 0.196500 ;
    PORT
      LAYER met2 ;
        RECT 455.030 0.000 455.310 4.000 ;
    END
  END sstreams_i[101]
  PIN sstreams_i[102]
    DIRECTION INPUT ;
    USE SIGNAL ;
    ANTENNAGATEAREA 0.196500 ;
    PORT
      LAYER met2 ;
        RECT 459.170 0.000 459.450 4.000 ;
    END
  END sstreams_i[102]
  PIN sstreams_i[103]
    DIRECTION INPUT ;
    USE SIGNAL ;
    ANTENNAGATEAREA 0.196500 ;
    PORT
      LAYER met2 ;
        RECT 463.310 0.000 463.590 4.000 ;
    END
  END sstreams_i[103]
  PIN sstreams_i[104]
    DIRECTION INPUT ;
    USE SIGNAL ;
    ANTENNAGATEAREA 0.196500 ;
    PORT
      LAYER met2 ;
        RECT 467.450 0.000 467.730 4.000 ;
    END
  END sstreams_i[104]
  PIN sstreams_i[105]
    DIRECTION INPUT ;
    USE SIGNAL ;
    ANTENNAGATEAREA 0.196500 ;
    PORT
      LAYER met2 ;
        RECT 471.590 0.000 471.870 4.000 ;
    END
  END sstreams_i[105]
  PIN sstreams_i[106]
    DIRECTION INPUT ;
    USE SIGNAL ;
    ANTENNAGATEAREA 0.196500 ;
    PORT
      LAYER met2 ;
        RECT 475.730 0.000 476.010 4.000 ;
    END
  END sstreams_i[106]
  PIN sstreams_i[107]
    DIRECTION INPUT ;
    USE SIGNAL ;
    ANTENNAGATEAREA 0.196500 ;
    PORT
      LAYER met2 ;
        RECT 479.870 0.000 480.150 4.000 ;
    END
  END sstreams_i[107]
  PIN sstreams_i[108]
    DIRECTION INPUT ;
    USE SIGNAL ;
    ANTENNAGATEAREA 0.196500 ;
    PORT
      LAYER met2 ;
        RECT 484.010 0.000 484.290 4.000 ;
    END
  END sstreams_i[108]
  PIN sstreams_i[109]
    DIRECTION INPUT ;
    USE SIGNAL ;
    ANTENNAGATEAREA 0.196500 ;
    PORT
      LAYER met2 ;
        RECT 488.150 0.000 488.430 4.000 ;
    END
  END sstreams_i[109]
  PIN sstreams_i[10]
    DIRECTION INPUT ;
    USE SIGNAL ;
    ANTENNAGATEAREA 0.196500 ;
    PORT
      LAYER met2 ;
        RECT 78.290 0.000 78.570 4.000 ;
    END
  END sstreams_i[10]
  PIN sstreams_i[110]
    DIRECTION INPUT ;
    USE SIGNAL ;
    ANTENNAGATEAREA 0.196500 ;
    PORT
      LAYER met2 ;
        RECT 492.290 0.000 492.570 4.000 ;
    END
  END sstreams_i[110]
  PIN sstreams_i[111]
    DIRECTION INPUT ;
    USE SIGNAL ;
    ANTENNAGATEAREA 0.196500 ;
    PORT
      LAYER met2 ;
        RECT 496.430 0.000 496.710 4.000 ;
    END
  END sstreams_i[111]
  PIN sstreams_i[112]
    DIRECTION INPUT ;
    USE SIGNAL ;
    ANTENNAGATEAREA 0.196500 ;
    PORT
      LAYER met2 ;
        RECT 500.570 0.000 500.850 4.000 ;
    END
  END sstreams_i[112]
  PIN sstreams_i[113]
    DIRECTION INPUT ;
    USE SIGNAL ;
    ANTENNAGATEAREA 0.196500 ;
    PORT
      LAYER met2 ;
        RECT 504.710 0.000 504.990 4.000 ;
    END
  END sstreams_i[113]
  PIN sstreams_i[114]
    DIRECTION INPUT ;
    USE SIGNAL ;
    ANTENNAGATEAREA 0.196500 ;
    PORT
      LAYER met2 ;
        RECT 508.850 0.000 509.130 4.000 ;
    END
  END sstreams_i[114]
  PIN sstreams_i[115]
    DIRECTION INPUT ;
    USE SIGNAL ;
    ANTENNAGATEAREA 0.196500 ;
    PORT
      LAYER met2 ;
        RECT 512.990 0.000 513.270 4.000 ;
    END
  END sstreams_i[115]
  PIN sstreams_i[116]
    DIRECTION INPUT ;
    USE SIGNAL ;
    ANTENNAGATEAREA 0.196500 ;
    PORT
      LAYER met2 ;
        RECT 517.130 0.000 517.410 4.000 ;
    END
  END sstreams_i[116]
  PIN sstreams_i[117]
    DIRECTION INPUT ;
    USE SIGNAL ;
    ANTENNAGATEAREA 0.196500 ;
    PORT
      LAYER met2 ;
        RECT 521.270 0.000 521.550 4.000 ;
    END
  END sstreams_i[117]
  PIN sstreams_i[118]
    DIRECTION INPUT ;
    USE SIGNAL ;
    ANTENNAGATEAREA 0.196500 ;
    PORT
      LAYER met2 ;
        RECT 525.410 0.000 525.690 4.000 ;
    END
  END sstreams_i[118]
  PIN sstreams_i[119]
    DIRECTION INPUT ;
    USE SIGNAL ;
    ANTENNAGATEAREA 0.196500 ;
    PORT
      LAYER met2 ;
        RECT 529.550 0.000 529.830 4.000 ;
    END
  END sstreams_i[119]
  PIN sstreams_i[11]
    DIRECTION INPUT ;
    USE SIGNAL ;
    ANTENNAGATEAREA 0.196500 ;
    PORT
      LAYER met2 ;
        RECT 82.430 0.000 82.710 4.000 ;
    END
  END sstreams_i[11]
  PIN sstreams_i[120]
    DIRECTION INPUT ;
    USE SIGNAL ;
    ANTENNAGATEAREA 0.196500 ;
    PORT
      LAYER met2 ;
        RECT 533.690 0.000 533.970 4.000 ;
    END
  END sstreams_i[120]
  PIN sstreams_i[121]
    DIRECTION INPUT ;
    USE SIGNAL ;
    ANTENNAGATEAREA 0.196500 ;
    PORT
      LAYER met2 ;
        RECT 537.830 0.000 538.110 4.000 ;
    END
  END sstreams_i[121]
  PIN sstreams_i[122]
    DIRECTION INPUT ;
    USE SIGNAL ;
    ANTENNAGATEAREA 0.196500 ;
    PORT
      LAYER met2 ;
        RECT 541.970 0.000 542.250 4.000 ;
    END
  END sstreams_i[122]
  PIN sstreams_i[123]
    DIRECTION INPUT ;
    USE SIGNAL ;
    ANTENNAGATEAREA 0.196500 ;
    PORT
      LAYER met2 ;
        RECT 546.110 0.000 546.390 4.000 ;
    END
  END sstreams_i[123]
  PIN sstreams_i[124]
    DIRECTION INPUT ;
    USE SIGNAL ;
    ANTENNAGATEAREA 0.196500 ;
    PORT
      LAYER met2 ;
        RECT 550.250 0.000 550.530 4.000 ;
    END
  END sstreams_i[124]
  PIN sstreams_i[125]
    DIRECTION INPUT ;
    USE SIGNAL ;
    ANTENNAGATEAREA 0.196500 ;
    PORT
      LAYER met2 ;
        RECT 554.390 0.000 554.670 4.000 ;
    END
  END sstreams_i[125]
  PIN sstreams_i[126]
    DIRECTION INPUT ;
    USE SIGNAL ;
    ANTENNAGATEAREA 0.196500 ;
    PORT
      LAYER met2 ;
        RECT 558.530 0.000 558.810 4.000 ;
    END
  END sstreams_i[126]
  PIN sstreams_i[127]
    DIRECTION INPUT ;
    USE SIGNAL ;
    ANTENNAGATEAREA 0.196500 ;
    PORT
      LAYER met2 ;
        RECT 562.670 0.000 562.950 4.000 ;
    END
  END sstreams_i[127]
  PIN sstreams_i[128]
    DIRECTION INPUT ;
    USE SIGNAL ;
    ANTENNAGATEAREA 0.196500 ;
    PORT
      LAYER met2 ;
        RECT 566.810 0.000 567.090 4.000 ;
    END
  END sstreams_i[128]
  PIN sstreams_i[129]
    DIRECTION INPUT ;
    USE SIGNAL ;
    ANTENNAGATEAREA 0.196500 ;
    PORT
      LAYER met2 ;
        RECT 570.950 0.000 571.230 4.000 ;
    END
  END sstreams_i[129]
  PIN sstreams_i[12]
    DIRECTION INPUT ;
    USE SIGNAL ;
    ANTENNAGATEAREA 0.196500 ;
    PORT
      LAYER met2 ;
        RECT 86.570 0.000 86.850 4.000 ;
    END
  END sstreams_i[12]
  PIN sstreams_i[130]
    DIRECTION INPUT ;
    USE SIGNAL ;
    ANTENNAGATEAREA 0.196500 ;
    PORT
      LAYER met2 ;
        RECT 575.090 0.000 575.370 4.000 ;
    END
  END sstreams_i[130]
  PIN sstreams_i[131]
    DIRECTION INPUT ;
    USE SIGNAL ;
    ANTENNAGATEAREA 0.196500 ;
    PORT
      LAYER met2 ;
        RECT 579.230 0.000 579.510 4.000 ;
    END
  END sstreams_i[131]
  PIN sstreams_i[132]
    DIRECTION INPUT ;
    USE SIGNAL ;
    ANTENNAGATEAREA 0.196500 ;
    PORT
      LAYER met2 ;
        RECT 583.370 0.000 583.650 4.000 ;
    END
  END sstreams_i[132]
  PIN sstreams_i[133]
    DIRECTION INPUT ;
    USE SIGNAL ;
    ANTENNAGATEAREA 0.196500 ;
    PORT
      LAYER met2 ;
        RECT 587.510 0.000 587.790 4.000 ;
    END
  END sstreams_i[133]
  PIN sstreams_i[134]
    DIRECTION INPUT ;
    USE SIGNAL ;
    ANTENNAGATEAREA 0.196500 ;
    PORT
      LAYER met2 ;
        RECT 591.650 0.000 591.930 4.000 ;
    END
  END sstreams_i[134]
  PIN sstreams_i[135]
    DIRECTION INPUT ;
    USE SIGNAL ;
    ANTENNAGATEAREA 0.196500 ;
    PORT
      LAYER met2 ;
        RECT 595.790 0.000 596.070 4.000 ;
    END
  END sstreams_i[135]
  PIN sstreams_i[136]
    DIRECTION INPUT ;
    USE SIGNAL ;
    ANTENNAGATEAREA 0.196500 ;
    PORT
      LAYER met2 ;
        RECT 599.930 0.000 600.210 4.000 ;
    END
  END sstreams_i[136]
  PIN sstreams_i[137]
    DIRECTION INPUT ;
    USE SIGNAL ;
    ANTENNAGATEAREA 0.196500 ;
    PORT
      LAYER met2 ;
        RECT 604.070 0.000 604.350 4.000 ;
    END
  END sstreams_i[137]
  PIN sstreams_i[138]
    DIRECTION INPUT ;
    USE SIGNAL ;
    ANTENNAGATEAREA 0.196500 ;
    PORT
      LAYER met2 ;
        RECT 608.210 0.000 608.490 4.000 ;
    END
  END sstreams_i[138]
  PIN sstreams_i[139]
    DIRECTION INPUT ;
    USE SIGNAL ;
    ANTENNAGATEAREA 0.196500 ;
    PORT
      LAYER met2 ;
        RECT 612.350 0.000 612.630 4.000 ;
    END
  END sstreams_i[139]
  PIN sstreams_i[13]
    DIRECTION INPUT ;
    USE SIGNAL ;
    ANTENNAGATEAREA 0.159000 ;
    PORT
      LAYER met2 ;
        RECT 90.710 0.000 90.990 4.000 ;
    END
  END sstreams_i[13]
  PIN sstreams_i[140]
    DIRECTION INPUT ;
    USE SIGNAL ;
    ANTENNAGATEAREA 0.196500 ;
    PORT
      LAYER met2 ;
        RECT 616.490 0.000 616.770 4.000 ;
    END
  END sstreams_i[140]
  PIN sstreams_i[141]
    DIRECTION INPUT ;
    USE SIGNAL ;
    ANTENNAGATEAREA 0.196500 ;
    PORT
      LAYER met2 ;
        RECT 620.630 0.000 620.910 4.000 ;
    END
  END sstreams_i[141]
  PIN sstreams_i[142]
    DIRECTION INPUT ;
    USE SIGNAL ;
    ANTENNAGATEAREA 0.196500 ;
    PORT
      LAYER met2 ;
        RECT 624.770 0.000 625.050 4.000 ;
    END
  END sstreams_i[142]
  PIN sstreams_i[143]
    DIRECTION INPUT ;
    USE SIGNAL ;
    ANTENNAGATEAREA 0.196500 ;
    PORT
      LAYER met2 ;
        RECT 628.910 0.000 629.190 4.000 ;
    END
  END sstreams_i[143]
  PIN sstreams_i[144]
    DIRECTION INPUT ;
    USE SIGNAL ;
    ANTENNAGATEAREA 0.196500 ;
    PORT
      LAYER met2 ;
        RECT 633.050 0.000 633.330 4.000 ;
    END
  END sstreams_i[144]
  PIN sstreams_i[145]
    DIRECTION INPUT ;
    USE SIGNAL ;
    ANTENNAGATEAREA 0.196500 ;
    PORT
      LAYER met2 ;
        RECT 637.190 0.000 637.470 4.000 ;
    END
  END sstreams_i[145]
  PIN sstreams_i[146]
    DIRECTION INPUT ;
    USE SIGNAL ;
    ANTENNAGATEAREA 0.196500 ;
    PORT
      LAYER met2 ;
        RECT 641.330 0.000 641.610 4.000 ;
    END
  END sstreams_i[146]
  PIN sstreams_i[147]
    DIRECTION INPUT ;
    USE SIGNAL ;
    ANTENNAGATEAREA 0.196500 ;
    PORT
      LAYER met2 ;
        RECT 645.470 0.000 645.750 4.000 ;
    END
  END sstreams_i[147]
  PIN sstreams_i[148]
    DIRECTION INPUT ;
    USE SIGNAL ;
    ANTENNAGATEAREA 0.196500 ;
    PORT
      LAYER met2 ;
        RECT 649.610 0.000 649.890 4.000 ;
    END
  END sstreams_i[148]
  PIN sstreams_i[149]
    DIRECTION INPUT ;
    USE SIGNAL ;
    ANTENNAGATEAREA 0.196500 ;
    PORT
      LAYER met2 ;
        RECT 653.750 0.000 654.030 4.000 ;
    END
  END sstreams_i[149]
  PIN sstreams_i[14]
    DIRECTION INPUT ;
    USE SIGNAL ;
    ANTENNAGATEAREA 0.196500 ;
    PORT
      LAYER met2 ;
        RECT 94.850 0.000 95.130 4.000 ;
    END
  END sstreams_i[14]
  PIN sstreams_i[150]
    DIRECTION INPUT ;
    USE SIGNAL ;
    ANTENNAGATEAREA 0.196500 ;
    PORT
      LAYER met2 ;
        RECT 657.890 0.000 658.170 4.000 ;
    END
  END sstreams_i[150]
  PIN sstreams_i[151]
    DIRECTION INPUT ;
    USE SIGNAL ;
    ANTENNAGATEAREA 0.196500 ;
    PORT
      LAYER met2 ;
        RECT 662.030 0.000 662.310 4.000 ;
    END
  END sstreams_i[151]
  PIN sstreams_i[152]
    DIRECTION INPUT ;
    USE SIGNAL ;
    ANTENNAGATEAREA 0.196500 ;
    PORT
      LAYER met2 ;
        RECT 666.170 0.000 666.450 4.000 ;
    END
  END sstreams_i[152]
  PIN sstreams_i[153]
    DIRECTION INPUT ;
    USE SIGNAL ;
    ANTENNAGATEAREA 0.196500 ;
    PORT
      LAYER met2 ;
        RECT 670.310 0.000 670.590 4.000 ;
    END
  END sstreams_i[153]
  PIN sstreams_i[154]
    DIRECTION INPUT ;
    USE SIGNAL ;
    ANTENNAGATEAREA 0.196500 ;
    PORT
      LAYER met2 ;
        RECT 674.450 0.000 674.730 4.000 ;
    END
  END sstreams_i[154]
  PIN sstreams_i[155]
    DIRECTION INPUT ;
    USE SIGNAL ;
    ANTENNAGATEAREA 0.196500 ;
    PORT
      LAYER met2 ;
        RECT 678.590 0.000 678.870 4.000 ;
    END
  END sstreams_i[155]
  PIN sstreams_i[156]
    DIRECTION INPUT ;
    USE SIGNAL ;
    ANTENNAGATEAREA 0.196500 ;
    PORT
      LAYER met2 ;
        RECT 682.730 0.000 683.010 4.000 ;
    END
  END sstreams_i[156]
  PIN sstreams_i[157]
    DIRECTION INPUT ;
    USE SIGNAL ;
    ANTENNAGATEAREA 0.196500 ;
    PORT
      LAYER met2 ;
        RECT 686.870 0.000 687.150 4.000 ;
    END
  END sstreams_i[157]
  PIN sstreams_i[158]
    DIRECTION INPUT ;
    USE SIGNAL ;
    ANTENNAGATEAREA 0.196500 ;
    PORT
      LAYER met2 ;
        RECT 691.010 0.000 691.290 4.000 ;
    END
  END sstreams_i[158]
  PIN sstreams_i[159]
    DIRECTION INPUT ;
    USE SIGNAL ;
    ANTENNAGATEAREA 0.196500 ;
    PORT
      LAYER met2 ;
        RECT 695.150 0.000 695.430 4.000 ;
    END
  END sstreams_i[159]
  PIN sstreams_i[15]
    DIRECTION INPUT ;
    USE SIGNAL ;
    ANTENNAGATEAREA 0.159000 ;
    PORT
      LAYER met2 ;
        RECT 98.990 0.000 99.270 4.000 ;
    END
  END sstreams_i[15]
  PIN sstreams_i[160]
    DIRECTION INPUT ;
    USE SIGNAL ;
    ANTENNAGATEAREA 0.196500 ;
    PORT
      LAYER met2 ;
        RECT 699.290 0.000 699.570 4.000 ;
    END
  END sstreams_i[160]
  PIN sstreams_i[161]
    DIRECTION INPUT ;
    USE SIGNAL ;
    ANTENNAGATEAREA 0.196500 ;
    PORT
      LAYER met2 ;
        RECT 703.430 0.000 703.710 4.000 ;
    END
  END sstreams_i[161]
  PIN sstreams_i[162]
    DIRECTION INPUT ;
    USE SIGNAL ;
    ANTENNAGATEAREA 0.196500 ;
    PORT
      LAYER met2 ;
        RECT 707.570 0.000 707.850 4.000 ;
    END
  END sstreams_i[162]
  PIN sstreams_i[163]
    DIRECTION INPUT ;
    USE SIGNAL ;
    ANTENNAGATEAREA 0.196500 ;
    PORT
      LAYER met2 ;
        RECT 711.710 0.000 711.990 4.000 ;
    END
  END sstreams_i[163]
  PIN sstreams_i[164]
    DIRECTION INPUT ;
    USE SIGNAL ;
    ANTENNAGATEAREA 0.196500 ;
    PORT
      LAYER met2 ;
        RECT 715.850 0.000 716.130 4.000 ;
    END
  END sstreams_i[164]
  PIN sstreams_i[165]
    DIRECTION INPUT ;
    USE SIGNAL ;
    ANTENNAGATEAREA 0.196500 ;
    PORT
      LAYER met2 ;
        RECT 719.990 0.000 720.270 4.000 ;
    END
  END sstreams_i[165]
  PIN sstreams_i[166]
    DIRECTION INPUT ;
    USE SIGNAL ;
    ANTENNAGATEAREA 0.196500 ;
    PORT
      LAYER met2 ;
        RECT 724.130 0.000 724.410 4.000 ;
    END
  END sstreams_i[166]
  PIN sstreams_i[167]
    DIRECTION INPUT ;
    USE SIGNAL ;
    ANTENNAGATEAREA 0.196500 ;
    PORT
      LAYER met2 ;
        RECT 728.270 0.000 728.550 4.000 ;
    END
  END sstreams_i[167]
  PIN sstreams_i[168]
    DIRECTION INPUT ;
    USE SIGNAL ;
    ANTENNAGATEAREA 0.196500 ;
    PORT
      LAYER met2 ;
        RECT 732.410 0.000 732.690 4.000 ;
    END
  END sstreams_i[168]
  PIN sstreams_i[169]
    DIRECTION INPUT ;
    USE SIGNAL ;
    ANTENNAGATEAREA 0.196500 ;
    PORT
      LAYER met2 ;
        RECT 736.550 0.000 736.830 4.000 ;
    END
  END sstreams_i[169]
  PIN sstreams_i[16]
    DIRECTION INPUT ;
    USE SIGNAL ;
    ANTENNAGATEAREA 0.196500 ;
    PORT
      LAYER met2 ;
        RECT 103.130 0.000 103.410 4.000 ;
    END
  END sstreams_i[16]
  PIN sstreams_i[170]
    DIRECTION INPUT ;
    USE SIGNAL ;
    ANTENNAGATEAREA 0.196500 ;
    PORT
      LAYER met2 ;
        RECT 740.690 0.000 740.970 4.000 ;
    END
  END sstreams_i[170]
  PIN sstreams_i[171]
    DIRECTION INPUT ;
    USE SIGNAL ;
    ANTENNAGATEAREA 0.196500 ;
    PORT
      LAYER met2 ;
        RECT 744.830 0.000 745.110 4.000 ;
    END
  END sstreams_i[171]
  PIN sstreams_i[172]
    DIRECTION INPUT ;
    USE SIGNAL ;
    ANTENNAGATEAREA 0.196500 ;
    PORT
      LAYER met2 ;
        RECT 748.970 0.000 749.250 4.000 ;
    END
  END sstreams_i[172]
  PIN sstreams_i[173]
    DIRECTION INPUT ;
    USE SIGNAL ;
    ANTENNAGATEAREA 0.196500 ;
    PORT
      LAYER met2 ;
        RECT 753.110 0.000 753.390 4.000 ;
    END
  END sstreams_i[173]
  PIN sstreams_i[174]
    DIRECTION INPUT ;
    USE SIGNAL ;
    ANTENNAGATEAREA 0.196500 ;
    PORT
      LAYER met2 ;
        RECT 757.250 0.000 757.530 4.000 ;
    END
  END sstreams_i[174]
  PIN sstreams_i[175]
    DIRECTION INPUT ;
    USE SIGNAL ;
    ANTENNAGATEAREA 0.196500 ;
    PORT
      LAYER met2 ;
        RECT 761.390 0.000 761.670 4.000 ;
    END
  END sstreams_i[175]
  PIN sstreams_i[176]
    DIRECTION INPUT ;
    USE SIGNAL ;
    ANTENNAGATEAREA 0.196500 ;
    PORT
      LAYER met2 ;
        RECT 765.530 0.000 765.810 4.000 ;
    END
  END sstreams_i[176]
  PIN sstreams_i[177]
    DIRECTION INPUT ;
    USE SIGNAL ;
    ANTENNAGATEAREA 0.196500 ;
    PORT
      LAYER met2 ;
        RECT 769.670 0.000 769.950 4.000 ;
    END
  END sstreams_i[177]
  PIN sstreams_i[178]
    DIRECTION INPUT ;
    USE SIGNAL ;
    ANTENNAGATEAREA 0.196500 ;
    PORT
      LAYER met2 ;
        RECT 773.810 0.000 774.090 4.000 ;
    END
  END sstreams_i[178]
  PIN sstreams_i[179]
    DIRECTION INPUT ;
    USE SIGNAL ;
    ANTENNAGATEAREA 0.196500 ;
    PORT
      LAYER met2 ;
        RECT 777.950 0.000 778.230 4.000 ;
    END
  END sstreams_i[179]
  PIN sstreams_i[17]
    DIRECTION INPUT ;
    USE SIGNAL ;
    ANTENNAGATEAREA 0.213000 ;
    PORT
      LAYER met2 ;
        RECT 107.270 0.000 107.550 4.000 ;
    END
  END sstreams_i[17]
  PIN sstreams_i[180]
    DIRECTION INPUT ;
    USE SIGNAL ;
    ANTENNAGATEAREA 0.213000 ;
    PORT
      LAYER met2 ;
        RECT 782.090 0.000 782.370 4.000 ;
    END
  END sstreams_i[180]
  PIN sstreams_i[181]
    DIRECTION INPUT ;
    USE SIGNAL ;
    ANTENNAGATEAREA 0.196500 ;
    PORT
      LAYER met2 ;
        RECT 786.230 0.000 786.510 4.000 ;
    END
  END sstreams_i[181]
  PIN sstreams_i[182]
    DIRECTION INPUT ;
    USE SIGNAL ;
    ANTENNAGATEAREA 0.196500 ;
    PORT
      LAYER met2 ;
        RECT 790.370 0.000 790.650 4.000 ;
    END
  END sstreams_i[182]
  PIN sstreams_i[183]
    DIRECTION INPUT ;
    USE SIGNAL ;
    ANTENNAGATEAREA 0.213000 ;
    PORT
      LAYER met2 ;
        RECT 794.510 0.000 794.790 4.000 ;
    END
  END sstreams_i[183]
  PIN sstreams_i[184]
    DIRECTION INPUT ;
    USE SIGNAL ;
    ANTENNAGATEAREA 0.196500 ;
    PORT
      LAYER met2 ;
        RECT 798.650 0.000 798.930 4.000 ;
    END
  END sstreams_i[184]
  PIN sstreams_i[185]
    DIRECTION INPUT ;
    USE SIGNAL ;
    ANTENNAGATEAREA 0.196500 ;
    PORT
      LAYER met2 ;
        RECT 802.790 0.000 803.070 4.000 ;
    END
  END sstreams_i[185]
  PIN sstreams_i[186]
    DIRECTION INPUT ;
    USE SIGNAL ;
    ANTENNAGATEAREA 0.196500 ;
    PORT
      LAYER met2 ;
        RECT 806.930 0.000 807.210 4.000 ;
    END
  END sstreams_i[186]
  PIN sstreams_i[187]
    DIRECTION INPUT ;
    USE SIGNAL ;
    ANTENNAGATEAREA 0.196500 ;
    PORT
      LAYER met2 ;
        RECT 811.070 0.000 811.350 4.000 ;
    END
  END sstreams_i[187]
  PIN sstreams_i[188]
    DIRECTION INPUT ;
    USE SIGNAL ;
    ANTENNAGATEAREA 0.196500 ;
    PORT
      LAYER met2 ;
        RECT 815.210 0.000 815.490 4.000 ;
    END
  END sstreams_i[188]
  PIN sstreams_i[189]
    DIRECTION INPUT ;
    USE SIGNAL ;
    ANTENNAGATEAREA 0.196500 ;
    PORT
      LAYER met2 ;
        RECT 819.350 0.000 819.630 4.000 ;
    END
  END sstreams_i[189]
  PIN sstreams_i[18]
    DIRECTION INPUT ;
    USE SIGNAL ;
    ANTENNAGATEAREA 0.213000 ;
    PORT
      LAYER met2 ;
        RECT 111.410 0.000 111.690 4.000 ;
    END
  END sstreams_i[18]
  PIN sstreams_i[190]
    DIRECTION INPUT ;
    USE SIGNAL ;
    ANTENNAGATEAREA 0.196500 ;
    PORT
      LAYER met2 ;
        RECT 823.490 0.000 823.770 4.000 ;
    END
  END sstreams_i[190]
  PIN sstreams_i[191]
    DIRECTION INPUT ;
    USE SIGNAL ;
    ANTENNAGATEAREA 0.196500 ;
    PORT
      LAYER met2 ;
        RECT 827.630 0.000 827.910 4.000 ;
    END
  END sstreams_i[191]
  PIN sstreams_i[192]
    DIRECTION INPUT ;
    USE SIGNAL ;
    ANTENNAGATEAREA 0.196500 ;
    PORT
      LAYER met2 ;
        RECT 831.770 0.000 832.050 4.000 ;
    END
  END sstreams_i[192]
  PIN sstreams_i[193]
    DIRECTION INPUT ;
    USE SIGNAL ;
    ANTENNAGATEAREA 0.196500 ;
    PORT
      LAYER met2 ;
        RECT 835.910 0.000 836.190 4.000 ;
    END
  END sstreams_i[193]
  PIN sstreams_i[194]
    DIRECTION INPUT ;
    USE SIGNAL ;
    ANTENNAGATEAREA 0.213000 ;
    PORT
      LAYER met2 ;
        RECT 840.050 0.000 840.330 4.000 ;
    END
  END sstreams_i[194]
  PIN sstreams_i[195]
    DIRECTION INPUT ;
    USE SIGNAL ;
    PORT
      LAYER met2 ;
        RECT 844.190 0.000 844.470 4.000 ;
    END
  END sstreams_i[195]
  PIN sstreams_i[196]
    DIRECTION INPUT ;
    USE SIGNAL ;
    ANTENNAGATEAREA 0.196500 ;
    PORT
      LAYER met2 ;
        RECT 848.330 0.000 848.610 4.000 ;
    END
  END sstreams_i[196]
  PIN sstreams_i[197]
    DIRECTION INPUT ;
    USE SIGNAL ;
    ANTENNAGATEAREA 0.196500 ;
    PORT
      LAYER met2 ;
        RECT 852.470 0.000 852.750 4.000 ;
    END
  END sstreams_i[197]
  PIN sstreams_i[198]
    DIRECTION INPUT ;
    USE SIGNAL ;
    ANTENNAGATEAREA 0.196500 ;
    PORT
      LAYER met2 ;
        RECT 856.610 0.000 856.890 4.000 ;
    END
  END sstreams_i[198]
  PIN sstreams_i[199]
    DIRECTION INPUT ;
    USE SIGNAL ;
    ANTENNAGATEAREA 0.196500 ;
    PORT
      LAYER met2 ;
        RECT 860.750 0.000 861.030 4.000 ;
    END
  END sstreams_i[199]
  PIN sstreams_i[19]
    DIRECTION INPUT ;
    USE SIGNAL ;
    ANTENNAGATEAREA 0.196500 ;
    PORT
      LAYER met2 ;
        RECT 115.550 0.000 115.830 4.000 ;
    END
  END sstreams_i[19]
  PIN sstreams_i[1]
    DIRECTION INPUT ;
    USE SIGNAL ;
    ANTENNAGATEAREA 0.159000 ;
    PORT
      LAYER met2 ;
        RECT 41.030 0.000 41.310 4.000 ;
    END
  END sstreams_i[1]
  PIN sstreams_i[200]
    DIRECTION INPUT ;
    USE SIGNAL ;
    ANTENNAGATEAREA 0.196500 ;
    PORT
      LAYER met2 ;
        RECT 864.890 0.000 865.170 4.000 ;
    END
  END sstreams_i[200]
  PIN sstreams_i[201]
    DIRECTION INPUT ;
    USE SIGNAL ;
    ANTENNAGATEAREA 0.196500 ;
    PORT
      LAYER met2 ;
        RECT 869.030 0.000 869.310 4.000 ;
    END
  END sstreams_i[201]
  PIN sstreams_i[202]
    DIRECTION INPUT ;
    USE SIGNAL ;
    ANTENNAGATEAREA 0.196500 ;
    PORT
      LAYER met2 ;
        RECT 873.170 0.000 873.450 4.000 ;
    END
  END sstreams_i[202]
  PIN sstreams_i[203]
    DIRECTION INPUT ;
    USE SIGNAL ;
    ANTENNAGATEAREA 0.196500 ;
    PORT
      LAYER met2 ;
        RECT 877.310 0.000 877.590 4.000 ;
    END
  END sstreams_i[203]
  PIN sstreams_i[204]
    DIRECTION INPUT ;
    USE SIGNAL ;
    ANTENNAGATEAREA 0.196500 ;
    PORT
      LAYER met2 ;
        RECT 881.450 0.000 881.730 4.000 ;
    END
  END sstreams_i[204]
  PIN sstreams_i[205]
    DIRECTION INPUT ;
    USE SIGNAL ;
    ANTENNAGATEAREA 0.196500 ;
    PORT
      LAYER met2 ;
        RECT 885.590 0.000 885.870 4.000 ;
    END
  END sstreams_i[205]
  PIN sstreams_i[206]
    DIRECTION INPUT ;
    USE SIGNAL ;
    ANTENNAGATEAREA 0.196500 ;
    PORT
      LAYER met2 ;
        RECT 889.730 0.000 890.010 4.000 ;
    END
  END sstreams_i[206]
  PIN sstreams_i[207]
    DIRECTION INPUT ;
    USE SIGNAL ;
    ANTENNAGATEAREA 0.196500 ;
    PORT
      LAYER met2 ;
        RECT 893.870 0.000 894.150 4.000 ;
    END
  END sstreams_i[207]
  PIN sstreams_i[208]
    DIRECTION INPUT ;
    USE SIGNAL ;
    ANTENNAGATEAREA 0.196500 ;
    PORT
      LAYER met2 ;
        RECT 898.010 0.000 898.290 4.000 ;
    END
  END sstreams_i[208]
  PIN sstreams_i[209]
    DIRECTION INPUT ;
    USE SIGNAL ;
    ANTENNAGATEAREA 0.196500 ;
    PORT
      LAYER met2 ;
        RECT 902.150 0.000 902.430 4.000 ;
    END
  END sstreams_i[209]
  PIN sstreams_i[20]
    DIRECTION INPUT ;
    USE SIGNAL ;
    ANTENNAGATEAREA 0.196500 ;
    PORT
      LAYER met2 ;
        RECT 119.690 0.000 119.970 4.000 ;
    END
  END sstreams_i[20]
  PIN sstreams_i[210]
    DIRECTION INPUT ;
    USE SIGNAL ;
    ANTENNAGATEAREA 0.196500 ;
    PORT
      LAYER met2 ;
        RECT 906.290 0.000 906.570 4.000 ;
    END
  END sstreams_i[210]
  PIN sstreams_i[211]
    DIRECTION INPUT ;
    USE SIGNAL ;
    ANTENNAGATEAREA 0.196500 ;
    PORT
      LAYER met2 ;
        RECT 910.430 0.000 910.710 4.000 ;
    END
  END sstreams_i[211]
  PIN sstreams_i[212]
    DIRECTION INPUT ;
    USE SIGNAL ;
    ANTENNAGATEAREA 0.126000 ;
    PORT
      LAYER met2 ;
        RECT 914.570 0.000 914.850 4.000 ;
    END
  END sstreams_i[212]
  PIN sstreams_i[213]
    DIRECTION INPUT ;
    USE SIGNAL ;
    ANTENNAGATEAREA 0.196500 ;
    PORT
      LAYER met2 ;
        RECT 918.710 0.000 918.990 4.000 ;
    END
  END sstreams_i[213]
  PIN sstreams_i[214]
    DIRECTION INPUT ;
    USE SIGNAL ;
    ANTENNAGATEAREA 0.196500 ;
    PORT
      LAYER met2 ;
        RECT 922.850 0.000 923.130 4.000 ;
    END
  END sstreams_i[214]
  PIN sstreams_i[215]
    DIRECTION INPUT ;
    USE SIGNAL ;
    ANTENNAGATEAREA 0.196500 ;
    PORT
      LAYER met2 ;
        RECT 926.990 0.000 927.270 4.000 ;
    END
  END sstreams_i[215]
  PIN sstreams_i[216]
    DIRECTION INPUT ;
    USE SIGNAL ;
    ANTENNAGATEAREA 0.196500 ;
    PORT
      LAYER met2 ;
        RECT 931.130 0.000 931.410 4.000 ;
    END
  END sstreams_i[216]
  PIN sstreams_i[217]
    DIRECTION INPUT ;
    USE SIGNAL ;
    ANTENNAGATEAREA 0.196500 ;
    PORT
      LAYER met2 ;
        RECT 935.270 0.000 935.550 4.000 ;
    END
  END sstreams_i[217]
  PIN sstreams_i[218]
    DIRECTION INPUT ;
    USE SIGNAL ;
    ANTENNAGATEAREA 0.196500 ;
    PORT
      LAYER met2 ;
        RECT 939.410 0.000 939.690 4.000 ;
    END
  END sstreams_i[218]
  PIN sstreams_i[219]
    DIRECTION INPUT ;
    USE SIGNAL ;
    ANTENNAGATEAREA 0.196500 ;
    PORT
      LAYER met2 ;
        RECT 943.550 0.000 943.830 4.000 ;
    END
  END sstreams_i[219]
  PIN sstreams_i[21]
    DIRECTION INPUT ;
    USE SIGNAL ;
    ANTENNAGATEAREA 0.196500 ;
    PORT
      LAYER met2 ;
        RECT 123.830 0.000 124.110 4.000 ;
    END
  END sstreams_i[21]
  PIN sstreams_i[220]
    DIRECTION INPUT ;
    USE SIGNAL ;
    ANTENNAGATEAREA 0.126000 ;
    PORT
      LAYER met2 ;
        RECT 947.690 0.000 947.970 4.000 ;
    END
  END sstreams_i[220]
  PIN sstreams_i[221]
    DIRECTION INPUT ;
    USE SIGNAL ;
    ANTENNAGATEAREA 0.213000 ;
    PORT
      LAYER met2 ;
        RECT 951.830 0.000 952.110 4.000 ;
    END
  END sstreams_i[221]
  PIN sstreams_i[222]
    DIRECTION INPUT ;
    USE SIGNAL ;
    ANTENNAGATEAREA 0.126000 ;
    PORT
      LAYER met2 ;
        RECT 955.970 0.000 956.250 4.000 ;
    END
  END sstreams_i[222]
  PIN sstreams_i[223]
    DIRECTION INPUT ;
    USE SIGNAL ;
    ANTENNAGATEAREA 0.196500 ;
    PORT
      LAYER met2 ;
        RECT 960.110 0.000 960.390 4.000 ;
    END
  END sstreams_i[223]
  PIN sstreams_i[224]
    DIRECTION INPUT ;
    USE SIGNAL ;
    ANTENNAGATEAREA 0.213000 ;
    PORT
      LAYER met2 ;
        RECT 964.250 0.000 964.530 4.000 ;
    END
  END sstreams_i[224]
  PIN sstreams_i[225]
    DIRECTION INPUT ;
    USE SIGNAL ;
    ANTENNAGATEAREA 0.213000 ;
    PORT
      LAYER met2 ;
        RECT 968.390 0.000 968.670 4.000 ;
    END
  END sstreams_i[225]
  PIN sstreams_i[226]
    DIRECTION INPUT ;
    USE SIGNAL ;
    ANTENNAGATEAREA 0.213000 ;
    PORT
      LAYER met2 ;
        RECT 972.530 0.000 972.810 4.000 ;
    END
  END sstreams_i[226]
  PIN sstreams_i[227]
    DIRECTION INPUT ;
    USE SIGNAL ;
    ANTENNAGATEAREA 0.213000 ;
    PORT
      LAYER met2 ;
        RECT 976.670 0.000 976.950 4.000 ;
    END
  END sstreams_i[227]
  PIN sstreams_i[228]
    DIRECTION INPUT ;
    USE SIGNAL ;
    ANTENNAGATEAREA 0.196500 ;
    PORT
      LAYER met2 ;
        RECT 980.810 0.000 981.090 4.000 ;
    END
  END sstreams_i[228]
  PIN sstreams_i[229]
    DIRECTION INPUT ;
    USE SIGNAL ;
    ANTENNAGATEAREA 0.213000 ;
    PORT
      LAYER met2 ;
        RECT 984.950 0.000 985.230 4.000 ;
    END
  END sstreams_i[229]
  PIN sstreams_i[22]
    DIRECTION INPUT ;
    USE SIGNAL ;
    ANTENNAGATEAREA 0.196500 ;
    PORT
      LAYER met2 ;
        RECT 127.970 0.000 128.250 4.000 ;
    END
  END sstreams_i[22]
  PIN sstreams_i[230]
    DIRECTION INPUT ;
    USE SIGNAL ;
    ANTENNAGATEAREA 0.213000 ;
    PORT
      LAYER met2 ;
        RECT 989.090 0.000 989.370 4.000 ;
    END
  END sstreams_i[230]
  PIN sstreams_i[231]
    DIRECTION INPUT ;
    USE SIGNAL ;
    ANTENNAGATEAREA 0.159000 ;
    PORT
      LAYER met2 ;
        RECT 993.230 0.000 993.510 4.000 ;
    END
  END sstreams_i[231]
  PIN sstreams_i[232]
    DIRECTION INPUT ;
    USE SIGNAL ;
    ANTENNAGATEAREA 0.196500 ;
    PORT
      LAYER met2 ;
        RECT 997.370 0.000 997.650 4.000 ;
    END
  END sstreams_i[232]
  PIN sstreams_i[233]
    DIRECTION INPUT ;
    USE SIGNAL ;
    ANTENNAGATEAREA 0.213000 ;
    PORT
      LAYER met2 ;
        RECT 1001.510 0.000 1001.790 4.000 ;
    END
  END sstreams_i[233]
  PIN sstreams_i[234]
    DIRECTION INPUT ;
    USE SIGNAL ;
    ANTENNAGATEAREA 0.196500 ;
    PORT
      LAYER met2 ;
        RECT 1005.650 0.000 1005.930 4.000 ;
    END
  END sstreams_i[234]
  PIN sstreams_i[235]
    DIRECTION INPUT ;
    USE SIGNAL ;
    ANTENNAGATEAREA 0.159000 ;
    PORT
      LAYER met2 ;
        RECT 1009.790 0.000 1010.070 4.000 ;
    END
  END sstreams_i[235]
  PIN sstreams_i[236]
    DIRECTION INPUT ;
    USE SIGNAL ;
    ANTENNAGATEAREA 0.159000 ;
    PORT
      LAYER met2 ;
        RECT 1013.930 0.000 1014.210 4.000 ;
    END
  END sstreams_i[236]
  PIN sstreams_i[237]
    DIRECTION INPUT ;
    USE SIGNAL ;
    ANTENNAGATEAREA 0.247500 ;
    PORT
      LAYER met2 ;
        RECT 1018.070 0.000 1018.350 4.000 ;
    END
  END sstreams_i[237]
  PIN sstreams_i[238]
    DIRECTION INPUT ;
    USE SIGNAL ;
    ANTENNAGATEAREA 0.247500 ;
    PORT
      LAYER met2 ;
        RECT 1022.210 0.000 1022.490 4.000 ;
    END
  END sstreams_i[238]
  PIN sstreams_i[239]
    DIRECTION INPUT ;
    USE SIGNAL ;
    ANTENNAGATEAREA 0.247500 ;
    PORT
      LAYER met2 ;
        RECT 1026.350 0.000 1026.630 4.000 ;
    END
  END sstreams_i[239]
  PIN sstreams_i[23]
    DIRECTION INPUT ;
    USE SIGNAL ;
    ANTENNAGATEAREA 0.196500 ;
    PORT
      LAYER met2 ;
        RECT 132.110 0.000 132.390 4.000 ;
    END
  END sstreams_i[23]
  PIN sstreams_i[240]
    DIRECTION INPUT ;
    USE SIGNAL ;
    ANTENNAGATEAREA 0.159000 ;
    PORT
      LAYER met2 ;
        RECT 1030.490 0.000 1030.770 4.000 ;
    END
  END sstreams_i[240]
  PIN sstreams_i[241]
    DIRECTION INPUT ;
    USE SIGNAL ;
    ANTENNAGATEAREA 0.159000 ;
    PORT
      LAYER met2 ;
        RECT 1034.630 0.000 1034.910 4.000 ;
    END
  END sstreams_i[241]
  PIN sstreams_i[242]
    DIRECTION INPUT ;
    USE SIGNAL ;
    ANTENNAGATEAREA 0.247500 ;
    PORT
      LAYER met2 ;
        RECT 1038.770 0.000 1039.050 4.000 ;
    END
  END sstreams_i[242]
  PIN sstreams_i[243]
    DIRECTION INPUT ;
    USE SIGNAL ;
    ANTENNAGATEAREA 0.213000 ;
    PORT
      LAYER met2 ;
        RECT 1042.910 0.000 1043.190 4.000 ;
    END
  END sstreams_i[243]
  PIN sstreams_i[244]
    DIRECTION INPUT ;
    USE SIGNAL ;
    ANTENNAGATEAREA 0.213000 ;
    PORT
      LAYER met2 ;
        RECT 1047.050 0.000 1047.330 4.000 ;
    END
  END sstreams_i[244]
  PIN sstreams_i[245]
    DIRECTION INPUT ;
    USE SIGNAL ;
    ANTENNAGATEAREA 0.213000 ;
    PORT
      LAYER met2 ;
        RECT 1051.190 0.000 1051.470 4.000 ;
    END
  END sstreams_i[245]
  PIN sstreams_i[246]
    DIRECTION INPUT ;
    USE SIGNAL ;
    ANTENNAGATEAREA 0.247500 ;
    PORT
      LAYER met2 ;
        RECT 1055.330 0.000 1055.610 4.000 ;
    END
  END sstreams_i[246]
  PIN sstreams_i[247]
    DIRECTION INPUT ;
    USE SIGNAL ;
    ANTENNAGATEAREA 0.247500 ;
    PORT
      LAYER met2 ;
        RECT 1059.470 0.000 1059.750 4.000 ;
    END
  END sstreams_i[247]
  PIN sstreams_i[248]
    DIRECTION INPUT ;
    USE SIGNAL ;
    ANTENNAGATEAREA 0.213000 ;
    PORT
      LAYER met2 ;
        RECT 1063.610 0.000 1063.890 4.000 ;
    END
  END sstreams_i[248]
  PIN sstreams_i[249]
    DIRECTION INPUT ;
    USE SIGNAL ;
    ANTENNAGATEAREA 0.213000 ;
    PORT
      LAYER met2 ;
        RECT 1067.750 0.000 1068.030 4.000 ;
    END
  END sstreams_i[249]
  PIN sstreams_i[24]
    DIRECTION INPUT ;
    USE SIGNAL ;
    ANTENNAGATEAREA 0.213000 ;
    PORT
      LAYER met2 ;
        RECT 136.250 0.000 136.530 4.000 ;
    END
  END sstreams_i[24]
  PIN sstreams_i[250]
    DIRECTION INPUT ;
    USE SIGNAL ;
    ANTENNAGATEAREA 0.247500 ;
    PORT
      LAYER met2 ;
        RECT 1071.890 0.000 1072.170 4.000 ;
    END
  END sstreams_i[250]
  PIN sstreams_i[251]
    DIRECTION INPUT ;
    USE SIGNAL ;
    ANTENNAGATEAREA 0.213000 ;
    PORT
      LAYER met2 ;
        RECT 1076.030 0.000 1076.310 4.000 ;
    END
  END sstreams_i[251]
  PIN sstreams_i[252]
    DIRECTION INPUT ;
    USE SIGNAL ;
    ANTENNAGATEAREA 0.213000 ;
    PORT
      LAYER met2 ;
        RECT 1080.170 0.000 1080.450 4.000 ;
    END
  END sstreams_i[252]
  PIN sstreams_i[253]
    DIRECTION INPUT ;
    USE SIGNAL ;
    ANTENNAGATEAREA 0.213000 ;
    PORT
      LAYER met2 ;
        RECT 1084.310 0.000 1084.590 4.000 ;
    END
  END sstreams_i[253]
  PIN sstreams_i[254]
    DIRECTION INPUT ;
    USE SIGNAL ;
    ANTENNAGATEAREA 0.213000 ;
    PORT
      LAYER met2 ;
        RECT 1088.450 0.000 1088.730 4.000 ;
    END
  END sstreams_i[254]
  PIN sstreams_i[255]
    DIRECTION INPUT ;
    USE SIGNAL ;
    ANTENNAGATEAREA 0.213000 ;
    PORT
      LAYER met2 ;
        RECT 1092.590 0.000 1092.870 4.000 ;
    END
  END sstreams_i[255]
  PIN sstreams_i[256]
    DIRECTION INPUT ;
    USE SIGNAL ;
    ANTENNAGATEAREA 0.213000 ;
    PORT
      LAYER met2 ;
        RECT 1096.730 0.000 1097.010 4.000 ;
    END
  END sstreams_i[256]
  PIN sstreams_i[257]
    DIRECTION INPUT ;
    USE SIGNAL ;
    ANTENNAGATEAREA 0.213000 ;
    PORT
      LAYER met2 ;
        RECT 1100.870 0.000 1101.150 4.000 ;
    END
  END sstreams_i[257]
  PIN sstreams_i[258]
    DIRECTION INPUT ;
    USE SIGNAL ;
    ANTENNAGATEAREA 0.213000 ;
    PORT
      LAYER met2 ;
        RECT 1105.010 0.000 1105.290 4.000 ;
    END
  END sstreams_i[258]
  PIN sstreams_i[259]
    DIRECTION INPUT ;
    USE SIGNAL ;
    ANTENNAGATEAREA 0.213000 ;
    PORT
      LAYER met2 ;
        RECT 1109.150 0.000 1109.430 4.000 ;
    END
  END sstreams_i[259]
  PIN sstreams_i[25]
    DIRECTION INPUT ;
    USE SIGNAL ;
    ANTENNAGATEAREA 0.159000 ;
    PORT
      LAYER met2 ;
        RECT 140.390 0.000 140.670 4.000 ;
    END
  END sstreams_i[25]
  PIN sstreams_i[260]
    DIRECTION INPUT ;
    USE SIGNAL ;
    ANTENNAGATEAREA 0.247500 ;
    PORT
      LAYER met2 ;
        RECT 1113.290 0.000 1113.570 4.000 ;
    END
  END sstreams_i[260]
  PIN sstreams_i[261]
    DIRECTION INPUT ;
    USE SIGNAL ;
    ANTENNAGATEAREA 0.213000 ;
    PORT
      LAYER met2 ;
        RECT 1117.430 0.000 1117.710 4.000 ;
    END
  END sstreams_i[261]
  PIN sstreams_i[262]
    DIRECTION INPUT ;
    USE SIGNAL ;
    ANTENNAGATEAREA 0.213000 ;
    PORT
      LAYER met2 ;
        RECT 1121.570 0.000 1121.850 4.000 ;
    END
  END sstreams_i[262]
  PIN sstreams_i[263]
    DIRECTION INPUT ;
    USE SIGNAL ;
    ANTENNAGATEAREA 0.213000 ;
    PORT
      LAYER met2 ;
        RECT 1125.710 0.000 1125.990 4.000 ;
    END
  END sstreams_i[263]
  PIN sstreams_i[264]
    DIRECTION INPUT ;
    USE SIGNAL ;
    ANTENNAGATEAREA 0.213000 ;
    PORT
      LAYER met2 ;
        RECT 1129.850 0.000 1130.130 4.000 ;
    END
  END sstreams_i[264]
  PIN sstreams_i[265]
    DIRECTION INPUT ;
    USE SIGNAL ;
    ANTENNAGATEAREA 0.213000 ;
    PORT
      LAYER met2 ;
        RECT 1133.990 0.000 1134.270 4.000 ;
    END
  END sstreams_i[265]
  PIN sstreams_i[266]
    DIRECTION INPUT ;
    USE SIGNAL ;
    ANTENNAGATEAREA 0.247500 ;
    PORT
      LAYER met2 ;
        RECT 1138.130 0.000 1138.410 4.000 ;
    END
  END sstreams_i[266]
  PIN sstreams_i[267]
    DIRECTION INPUT ;
    USE SIGNAL ;
    ANTENNAGATEAREA 0.247500 ;
    PORT
      LAYER met2 ;
        RECT 1142.270 0.000 1142.550 4.000 ;
    END
  END sstreams_i[267]
  PIN sstreams_i[268]
    DIRECTION INPUT ;
    USE SIGNAL ;
    ANTENNAGATEAREA 0.213000 ;
    PORT
      LAYER met2 ;
        RECT 1146.410 0.000 1146.690 4.000 ;
    END
  END sstreams_i[268]
  PIN sstreams_i[269]
    DIRECTION INPUT ;
    USE SIGNAL ;
    ANTENNAGATEAREA 0.213000 ;
    PORT
      LAYER met2 ;
        RECT 1150.550 0.000 1150.830 4.000 ;
    END
  END sstreams_i[269]
  PIN sstreams_i[26]
    DIRECTION INPUT ;
    USE SIGNAL ;
    ANTENNAGATEAREA 0.159000 ;
    PORT
      LAYER met2 ;
        RECT 144.530 0.000 144.810 4.000 ;
    END
  END sstreams_i[26]
  PIN sstreams_i[270]
    DIRECTION INPUT ;
    USE SIGNAL ;
    ANTENNAGATEAREA 0.213000 ;
    PORT
      LAYER met2 ;
        RECT 1154.690 0.000 1154.970 4.000 ;
    END
  END sstreams_i[270]
  PIN sstreams_i[271]
    DIRECTION INPUT ;
    USE SIGNAL ;
    ANTENNAGATEAREA 0.213000 ;
    PORT
      LAYER met2 ;
        RECT 1158.830 0.000 1159.110 4.000 ;
    END
  END sstreams_i[271]
  PIN sstreams_i[272]
    DIRECTION INPUT ;
    USE SIGNAL ;
    ANTENNAGATEAREA 0.213000 ;
    PORT
      LAYER met2 ;
        RECT 1162.970 0.000 1163.250 4.000 ;
    END
  END sstreams_i[272]
  PIN sstreams_i[273]
    DIRECTION INPUT ;
    USE SIGNAL ;
    ANTENNAGATEAREA 0.213000 ;
    PORT
      LAYER met2 ;
        RECT 1167.110 0.000 1167.390 4.000 ;
    END
  END sstreams_i[273]
  PIN sstreams_i[274]
    DIRECTION INPUT ;
    USE SIGNAL ;
    ANTENNAGATEAREA 0.213000 ;
    PORT
      LAYER met2 ;
        RECT 1171.250 0.000 1171.530 4.000 ;
    END
  END sstreams_i[274]
  PIN sstreams_i[275]
    DIRECTION INPUT ;
    USE SIGNAL ;
    ANTENNAGATEAREA 0.213000 ;
    PORT
      LAYER met2 ;
        RECT 1175.390 0.000 1175.670 4.000 ;
    END
  END sstreams_i[275]
  PIN sstreams_i[276]
    DIRECTION INPUT ;
    USE SIGNAL ;
    ANTENNAGATEAREA 0.213000 ;
    PORT
      LAYER met2 ;
        RECT 1179.530 0.000 1179.810 4.000 ;
    END
  END sstreams_i[276]
  PIN sstreams_i[277]
    DIRECTION INPUT ;
    USE SIGNAL ;
    ANTENNAGATEAREA 0.213000 ;
    PORT
      LAYER met2 ;
        RECT 1183.670 0.000 1183.950 4.000 ;
    END
  END sstreams_i[277]
  PIN sstreams_i[278]
    DIRECTION INPUT ;
    USE SIGNAL ;
    ANTENNAGATEAREA 0.426000 ;
    PORT
      LAYER met2 ;
        RECT 1187.810 0.000 1188.090 4.000 ;
    END
  END sstreams_i[278]
  PIN sstreams_i[279]
    DIRECTION INPUT ;
    USE SIGNAL ;
    ANTENNAGATEAREA 0.213000 ;
    PORT
      LAYER met2 ;
        RECT 1191.950 0.000 1192.230 4.000 ;
    END
  END sstreams_i[279]
  PIN sstreams_i[27]
    DIRECTION INPUT ;
    USE SIGNAL ;
    ANTENNAGATEAREA 0.159000 ;
    PORT
      LAYER met2 ;
        RECT 148.670 0.000 148.950 4.000 ;
    END
  END sstreams_i[27]
  PIN sstreams_i[280]
    DIRECTION INPUT ;
    USE SIGNAL ;
    ANTENNAGATEAREA 0.247500 ;
    PORT
      LAYER met2 ;
        RECT 1196.090 0.000 1196.370 4.000 ;
    END
  END sstreams_i[280]
  PIN sstreams_i[281]
    DIRECTION INPUT ;
    USE SIGNAL ;
    ANTENNAGATEAREA 0.426000 ;
    PORT
      LAYER met2 ;
        RECT 1200.230 0.000 1200.510 4.000 ;
    END
  END sstreams_i[281]
  PIN sstreams_i[282]
    DIRECTION INPUT ;
    USE SIGNAL ;
    ANTENNAGATEAREA 0.247500 ;
    PORT
      LAYER met2 ;
        RECT 1204.370 0.000 1204.650 4.000 ;
    END
  END sstreams_i[282]
  PIN sstreams_i[283]
    DIRECTION INPUT ;
    USE SIGNAL ;
    ANTENNAGATEAREA 0.247500 ;
    PORT
      LAYER met2 ;
        RECT 1208.510 0.000 1208.790 4.000 ;
    END
  END sstreams_i[283]
  PIN sstreams_i[284]
    DIRECTION INPUT ;
    USE SIGNAL ;
    ANTENNAGATEAREA 0.213000 ;
    PORT
      LAYER met2 ;
        RECT 1212.650 0.000 1212.930 4.000 ;
    END
  END sstreams_i[284]
  PIN sstreams_i[285]
    DIRECTION INPUT ;
    USE SIGNAL ;
    ANTENNAGATEAREA 0.213000 ;
    PORT
      LAYER met2 ;
        RECT 1216.790 0.000 1217.070 4.000 ;
    END
  END sstreams_i[285]
  PIN sstreams_i[286]
    DIRECTION INPUT ;
    USE SIGNAL ;
    ANTENNAGATEAREA 0.213000 ;
    PORT
      LAYER met2 ;
        RECT 1220.930 0.000 1221.210 4.000 ;
    END
  END sstreams_i[286]
  PIN sstreams_i[287]
    DIRECTION INPUT ;
    USE SIGNAL ;
    ANTENNAGATEAREA 0.213000 ;
    PORT
      LAYER met2 ;
        RECT 1225.070 0.000 1225.350 4.000 ;
    END
  END sstreams_i[287]
  PIN sstreams_i[288]
    DIRECTION INPUT ;
    USE SIGNAL ;
    ANTENNAGATEAREA 0.213000 ;
    PORT
      LAYER met2 ;
        RECT 1229.210 0.000 1229.490 4.000 ;
    END
  END sstreams_i[288]
  PIN sstreams_i[289]
    DIRECTION INPUT ;
    USE SIGNAL ;
    ANTENNAGATEAREA 0.213000 ;
    PORT
      LAYER met2 ;
        RECT 1233.350 0.000 1233.630 4.000 ;
    END
  END sstreams_i[289]
  PIN sstreams_i[28]
    DIRECTION INPUT ;
    USE SIGNAL ;
    ANTENNAGATEAREA 0.213000 ;
    PORT
      LAYER met2 ;
        RECT 152.810 0.000 153.090 4.000 ;
    END
  END sstreams_i[28]
  PIN sstreams_i[290]
    DIRECTION INPUT ;
    USE SIGNAL ;
    ANTENNAGATEAREA 0.213000 ;
    PORT
      LAYER met2 ;
        RECT 1237.490 0.000 1237.770 4.000 ;
    END
  END sstreams_i[290]
  PIN sstreams_i[291]
    DIRECTION INPUT ;
    USE SIGNAL ;
    ANTENNAGATEAREA 0.213000 ;
    PORT
      LAYER met2 ;
        RECT 1241.630 0.000 1241.910 4.000 ;
    END
  END sstreams_i[291]
  PIN sstreams_i[292]
    DIRECTION INPUT ;
    USE SIGNAL ;
    ANTENNAGATEAREA 0.495000 ;
    PORT
      LAYER met2 ;
        RECT 1245.770 0.000 1246.050 4.000 ;
    END
  END sstreams_i[292]
  PIN sstreams_i[293]
    DIRECTION INPUT ;
    USE SIGNAL ;
    PORT
      LAYER met2 ;
        RECT 1249.910 0.000 1250.190 4.000 ;
    END
  END sstreams_i[293]
  PIN sstreams_i[29]
    DIRECTION INPUT ;
    USE SIGNAL ;
    ANTENNAGATEAREA 0.213000 ;
    PORT
      LAYER met2 ;
        RECT 156.950 0.000 157.230 4.000 ;
    END
  END sstreams_i[29]
  PIN sstreams_i[2]
    DIRECTION INPUT ;
    USE SIGNAL ;
    ANTENNAGATEAREA 0.159000 ;
    PORT
      LAYER met2 ;
        RECT 45.170 0.000 45.450 4.000 ;
    END
  END sstreams_i[2]
  PIN sstreams_i[30]
    DIRECTION INPUT ;
    USE SIGNAL ;
    ANTENNAGATEAREA 0.213000 ;
    PORT
      LAYER met2 ;
        RECT 161.090 0.000 161.370 4.000 ;
    END
  END sstreams_i[30]
  PIN sstreams_i[31]
    DIRECTION INPUT ;
    USE SIGNAL ;
    ANTENNAGATEAREA 0.126000 ;
    PORT
      LAYER met2 ;
        RECT 165.230 0.000 165.510 4.000 ;
    END
  END sstreams_i[31]
  PIN sstreams_i[32]
    DIRECTION INPUT ;
    USE SIGNAL ;
    ANTENNAGATEAREA 0.213000 ;
    PORT
      LAYER met2 ;
        RECT 169.370 0.000 169.650 4.000 ;
    END
  END sstreams_i[32]
  PIN sstreams_i[33]
    DIRECTION INPUT ;
    USE SIGNAL ;
    ANTENNAGATEAREA 0.213000 ;
    PORT
      LAYER met2 ;
        RECT 173.510 0.000 173.790 4.000 ;
    END
  END sstreams_i[33]
  PIN sstreams_i[34]
    DIRECTION INPUT ;
    USE SIGNAL ;
    ANTENNAGATEAREA 0.213000 ;
    PORT
      LAYER met2 ;
        RECT 177.650 0.000 177.930 4.000 ;
    END
  END sstreams_i[34]
  PIN sstreams_i[35]
    DIRECTION INPUT ;
    USE SIGNAL ;
    ANTENNAGATEAREA 0.159000 ;
    PORT
      LAYER met2 ;
        RECT 181.790 0.000 182.070 4.000 ;
    END
  END sstreams_i[35]
  PIN sstreams_i[36]
    DIRECTION INPUT ;
    USE SIGNAL ;
    ANTENNAGATEAREA 0.159000 ;
    PORT
      LAYER met2 ;
        RECT 185.930 0.000 186.210 4.000 ;
    END
  END sstreams_i[36]
  PIN sstreams_i[37]
    DIRECTION INPUT ;
    USE SIGNAL ;
    ANTENNAGATEAREA 0.126000 ;
    PORT
      LAYER met2 ;
        RECT 190.070 0.000 190.350 4.000 ;
    END
  END sstreams_i[37]
  PIN sstreams_i[38]
    DIRECTION INPUT ;
    USE SIGNAL ;
    ANTENNAGATEAREA 0.159000 ;
    PORT
      LAYER met2 ;
        RECT 194.210 0.000 194.490 4.000 ;
    END
  END sstreams_i[38]
  PIN sstreams_i[39]
    DIRECTION INPUT ;
    USE SIGNAL ;
    ANTENNAGATEAREA 0.213000 ;
    PORT
      LAYER met2 ;
        RECT 198.350 0.000 198.630 4.000 ;
    END
  END sstreams_i[39]
  PIN sstreams_i[3]
    DIRECTION INPUT ;
    USE SIGNAL ;
    ANTENNAGATEAREA 0.159000 ;
    PORT
      LAYER met2 ;
        RECT 49.310 0.000 49.590 4.000 ;
    END
  END sstreams_i[3]
  PIN sstreams_i[40]
    DIRECTION INPUT ;
    USE SIGNAL ;
    ANTENNAGATEAREA 0.213000 ;
    PORT
      LAYER met2 ;
        RECT 202.490 0.000 202.770 4.000 ;
    END
  END sstreams_i[40]
  PIN sstreams_i[41]
    DIRECTION INPUT ;
    USE SIGNAL ;
    ANTENNAGATEAREA 0.213000 ;
    PORT
      LAYER met2 ;
        RECT 206.630 0.000 206.910 4.000 ;
    END
  END sstreams_i[41]
  PIN sstreams_i[42]
    DIRECTION INPUT ;
    USE SIGNAL ;
    ANTENNAGATEAREA 0.247500 ;
    PORT
      LAYER met2 ;
        RECT 210.770 0.000 211.050 4.000 ;
    END
  END sstreams_i[42]
  PIN sstreams_i[43]
    DIRECTION INPUT ;
    USE SIGNAL ;
    ANTENNAGATEAREA 0.159000 ;
    PORT
      LAYER met2 ;
        RECT 214.910 0.000 215.190 4.000 ;
    END
  END sstreams_i[43]
  PIN sstreams_i[44]
    DIRECTION INPUT ;
    USE SIGNAL ;
    ANTENNAGATEAREA 0.247500 ;
    PORT
      LAYER met2 ;
        RECT 219.050 0.000 219.330 4.000 ;
    END
  END sstreams_i[44]
  PIN sstreams_i[45]
    DIRECTION INPUT ;
    USE SIGNAL ;
    ANTENNAGATEAREA 0.247500 ;
    PORT
      LAYER met2 ;
        RECT 223.190 0.000 223.470 4.000 ;
    END
  END sstreams_i[45]
  PIN sstreams_i[46]
    DIRECTION INPUT ;
    USE SIGNAL ;
    ANTENNAGATEAREA 0.159000 ;
    PORT
      LAYER met2 ;
        RECT 227.330 0.000 227.610 4.000 ;
    END
  END sstreams_i[46]
  PIN sstreams_i[47]
    DIRECTION INPUT ;
    USE SIGNAL ;
    ANTENNAGATEAREA 0.247500 ;
    PORT
      LAYER met2 ;
        RECT 231.470 0.000 231.750 4.000 ;
    END
  END sstreams_i[47]
  PIN sstreams_i[48]
    DIRECTION INPUT ;
    USE SIGNAL ;
    ANTENNAGATEAREA 0.213000 ;
    PORT
      LAYER met2 ;
        RECT 235.610 0.000 235.890 4.000 ;
    END
  END sstreams_i[48]
  PIN sstreams_i[49]
    DIRECTION INPUT ;
    USE SIGNAL ;
    ANTENNAGATEAREA 0.213000 ;
    PORT
      LAYER met2 ;
        RECT 239.750 0.000 240.030 4.000 ;
    END
  END sstreams_i[49]
  PIN sstreams_i[4]
    DIRECTION INPUT ;
    USE SIGNAL ;
    ANTENNAGATEAREA 0.159000 ;
    PORT
      LAYER met2 ;
        RECT 53.450 0.000 53.730 4.000 ;
    END
  END sstreams_i[4]
  PIN sstreams_i[50]
    DIRECTION INPUT ;
    USE SIGNAL ;
    ANTENNAGATEAREA 0.247500 ;
    PORT
      LAYER met2 ;
        RECT 243.890 0.000 244.170 4.000 ;
    END
  END sstreams_i[50]
  PIN sstreams_i[51]
    DIRECTION INPUT ;
    USE SIGNAL ;
    ANTENNAGATEAREA 0.247500 ;
    PORT
      LAYER met2 ;
        RECT 248.030 0.000 248.310 4.000 ;
    END
  END sstreams_i[51]
  PIN sstreams_i[52]
    DIRECTION INPUT ;
    USE SIGNAL ;
    ANTENNAGATEAREA 0.213000 ;
    PORT
      LAYER met2 ;
        RECT 252.170 0.000 252.450 4.000 ;
    END
  END sstreams_i[52]
  PIN sstreams_i[53]
    DIRECTION INPUT ;
    USE SIGNAL ;
    ANTENNAGATEAREA 0.213000 ;
    PORT
      LAYER met2 ;
        RECT 256.310 0.000 256.590 4.000 ;
    END
  END sstreams_i[53]
  PIN sstreams_i[54]
    DIRECTION INPUT ;
    USE SIGNAL ;
    ANTENNAGATEAREA 0.196500 ;
    PORT
      LAYER met2 ;
        RECT 260.450 0.000 260.730 4.000 ;
    END
  END sstreams_i[54]
  PIN sstreams_i[55]
    DIRECTION INPUT ;
    USE SIGNAL ;
    ANTENNAGATEAREA 0.247500 ;
    PORT
      LAYER met2 ;
        RECT 264.590 0.000 264.870 4.000 ;
    END
  END sstreams_i[55]
  PIN sstreams_i[56]
    DIRECTION INPUT ;
    USE SIGNAL ;
    ANTENNAGATEAREA 0.213000 ;
    PORT
      LAYER met2 ;
        RECT 268.730 0.000 269.010 4.000 ;
    END
  END sstreams_i[56]
  PIN sstreams_i[57]
    DIRECTION INPUT ;
    USE SIGNAL ;
    ANTENNAGATEAREA 0.213000 ;
    PORT
      LAYER met2 ;
        RECT 272.870 0.000 273.150 4.000 ;
    END
  END sstreams_i[57]
  PIN sstreams_i[58]
    DIRECTION INPUT ;
    USE SIGNAL ;
    ANTENNAGATEAREA 0.213000 ;
    PORT
      LAYER met2 ;
        RECT 277.010 0.000 277.290 4.000 ;
    END
  END sstreams_i[58]
  PIN sstreams_i[59]
    DIRECTION INPUT ;
    USE SIGNAL ;
    ANTENNAGATEAREA 0.247500 ;
    PORT
      LAYER met2 ;
        RECT 281.150 0.000 281.430 4.000 ;
    END
  END sstreams_i[59]
  PIN sstreams_i[5]
    DIRECTION INPUT ;
    USE SIGNAL ;
    ANTENNAGATEAREA 0.196500 ;
    PORT
      LAYER met2 ;
        RECT 57.590 0.000 57.870 4.000 ;
    END
  END sstreams_i[5]
  PIN sstreams_i[60]
    DIRECTION INPUT ;
    USE SIGNAL ;
    ANTENNAGATEAREA 0.247500 ;
    PORT
      LAYER met2 ;
        RECT 285.290 0.000 285.570 4.000 ;
    END
  END sstreams_i[60]
  PIN sstreams_i[61]
    DIRECTION INPUT ;
    USE SIGNAL ;
    ANTENNAGATEAREA 0.247500 ;
    PORT
      LAYER met2 ;
        RECT 289.430 0.000 289.710 4.000 ;
    END
  END sstreams_i[61]
  PIN sstreams_i[62]
    DIRECTION INPUT ;
    USE SIGNAL ;
    ANTENNAGATEAREA 0.213000 ;
    PORT
      LAYER met2 ;
        RECT 293.570 0.000 293.850 4.000 ;
    END
  END sstreams_i[62]
  PIN sstreams_i[63]
    DIRECTION INPUT ;
    USE SIGNAL ;
    ANTENNAGATEAREA 0.247500 ;
    PORT
      LAYER met2 ;
        RECT 297.710 0.000 297.990 4.000 ;
    END
  END sstreams_i[63]
  PIN sstreams_i[64]
    DIRECTION INPUT ;
    USE SIGNAL ;
    ANTENNAGATEAREA 0.196500 ;
    PORT
      LAYER met2 ;
        RECT 301.850 0.000 302.130 4.000 ;
    END
  END sstreams_i[64]
  PIN sstreams_i[65]
    DIRECTION INPUT ;
    USE SIGNAL ;
    ANTENNAGATEAREA 0.213000 ;
    PORT
      LAYER met2 ;
        RECT 305.990 0.000 306.270 4.000 ;
    END
  END sstreams_i[65]
  PIN sstreams_i[66]
    DIRECTION INPUT ;
    USE SIGNAL ;
    ANTENNAGATEAREA 0.247500 ;
    PORT
      LAYER met2 ;
        RECT 310.130 0.000 310.410 4.000 ;
    END
  END sstreams_i[66]
  PIN sstreams_i[67]
    DIRECTION INPUT ;
    USE SIGNAL ;
    ANTENNAGATEAREA 0.213000 ;
    PORT
      LAYER met2 ;
        RECT 314.270 0.000 314.550 4.000 ;
    END
  END sstreams_i[67]
  PIN sstreams_i[68]
    DIRECTION INPUT ;
    USE SIGNAL ;
    ANTENNAGATEAREA 0.213000 ;
    PORT
      LAYER met2 ;
        RECT 318.410 0.000 318.690 4.000 ;
    END
  END sstreams_i[68]
  PIN sstreams_i[69]
    DIRECTION INPUT ;
    USE SIGNAL ;
    ANTENNAGATEAREA 0.213000 ;
    PORT
      LAYER met2 ;
        RECT 322.550 0.000 322.830 4.000 ;
    END
  END sstreams_i[69]
  PIN sstreams_i[6]
    DIRECTION INPUT ;
    USE SIGNAL ;
    ANTENNAGATEAREA 0.159000 ;
    PORT
      LAYER met2 ;
        RECT 61.730 0.000 62.010 4.000 ;
    END
  END sstreams_i[6]
  PIN sstreams_i[70]
    DIRECTION INPUT ;
    USE SIGNAL ;
    ANTENNAGATEAREA 0.159000 ;
    PORT
      LAYER met2 ;
        RECT 326.690 0.000 326.970 4.000 ;
    END
  END sstreams_i[70]
  PIN sstreams_i[71]
    DIRECTION INPUT ;
    USE SIGNAL ;
    ANTENNAGATEAREA 0.213000 ;
    PORT
      LAYER met2 ;
        RECT 330.830 0.000 331.110 4.000 ;
    END
  END sstreams_i[71]
  PIN sstreams_i[72]
    DIRECTION INPUT ;
    USE SIGNAL ;
    ANTENNAGATEAREA 0.196500 ;
    PORT
      LAYER met2 ;
        RECT 334.970 0.000 335.250 4.000 ;
    END
  END sstreams_i[72]
  PIN sstreams_i[73]
    DIRECTION INPUT ;
    USE SIGNAL ;
    ANTENNAGATEAREA 0.196500 ;
    PORT
      LAYER met2 ;
        RECT 339.110 0.000 339.390 4.000 ;
    END
  END sstreams_i[73]
  PIN sstreams_i[74]
    DIRECTION INPUT ;
    USE SIGNAL ;
    ANTENNAGATEAREA 0.196500 ;
    PORT
      LAYER met2 ;
        RECT 343.250 0.000 343.530 4.000 ;
    END
  END sstreams_i[74]
  PIN sstreams_i[75]
    DIRECTION INPUT ;
    USE SIGNAL ;
    ANTENNAGATEAREA 0.196500 ;
    PORT
      LAYER met2 ;
        RECT 347.390 0.000 347.670 4.000 ;
    END
  END sstreams_i[75]
  PIN sstreams_i[76]
    DIRECTION INPUT ;
    USE SIGNAL ;
    ANTENNAGATEAREA 0.196500 ;
    PORT
      LAYER met2 ;
        RECT 351.530 0.000 351.810 4.000 ;
    END
  END sstreams_i[76]
  PIN sstreams_i[77]
    DIRECTION INPUT ;
    USE SIGNAL ;
    ANTENNAGATEAREA 0.196500 ;
    PORT
      LAYER met2 ;
        RECT 355.670 0.000 355.950 4.000 ;
    END
  END sstreams_i[77]
  PIN sstreams_i[78]
    DIRECTION INPUT ;
    USE SIGNAL ;
    ANTENNAGATEAREA 0.196500 ;
    PORT
      LAYER met2 ;
        RECT 359.810 0.000 360.090 4.000 ;
    END
  END sstreams_i[78]
  PIN sstreams_i[79]
    DIRECTION INPUT ;
    USE SIGNAL ;
    ANTENNAGATEAREA 0.196500 ;
    PORT
      LAYER met2 ;
        RECT 363.950 0.000 364.230 4.000 ;
    END
  END sstreams_i[79]
  PIN sstreams_i[7]
    DIRECTION INPUT ;
    USE SIGNAL ;
    ANTENNAGATEAREA 0.159000 ;
    PORT
      LAYER met2 ;
        RECT 65.870 0.000 66.150 4.000 ;
    END
  END sstreams_i[7]
  PIN sstreams_i[80]
    DIRECTION INPUT ;
    USE SIGNAL ;
    ANTENNAGATEAREA 0.126000 ;
    PORT
      LAYER met2 ;
        RECT 368.090 0.000 368.370 4.000 ;
    END
  END sstreams_i[80]
  PIN sstreams_i[81]
    DIRECTION INPUT ;
    USE SIGNAL ;
    ANTENNAGATEAREA 0.196500 ;
    PORT
      LAYER met2 ;
        RECT 372.230 0.000 372.510 4.000 ;
    END
  END sstreams_i[81]
  PIN sstreams_i[82]
    DIRECTION INPUT ;
    USE SIGNAL ;
    ANTENNAGATEAREA 0.196500 ;
    PORT
      LAYER met2 ;
        RECT 376.370 0.000 376.650 4.000 ;
    END
  END sstreams_i[82]
  PIN sstreams_i[83]
    DIRECTION INPUT ;
    USE SIGNAL ;
    ANTENNAGATEAREA 0.196500 ;
    PORT
      LAYER met2 ;
        RECT 380.510 0.000 380.790 4.000 ;
    END
  END sstreams_i[83]
  PIN sstreams_i[84]
    DIRECTION INPUT ;
    USE SIGNAL ;
    ANTENNAGATEAREA 0.126000 ;
    PORT
      LAYER met2 ;
        RECT 384.650 0.000 384.930 4.000 ;
    END
  END sstreams_i[84]
  PIN sstreams_i[85]
    DIRECTION INPUT ;
    USE SIGNAL ;
    ANTENNAGATEAREA 0.213000 ;
    PORT
      LAYER met2 ;
        RECT 388.790 0.000 389.070 4.000 ;
    END
  END sstreams_i[85]
  PIN sstreams_i[86]
    DIRECTION INPUT ;
    USE SIGNAL ;
    ANTENNAGATEAREA 0.213000 ;
    PORT
      LAYER met2 ;
        RECT 392.930 0.000 393.210 4.000 ;
    END
  END sstreams_i[86]
  PIN sstreams_i[87]
    DIRECTION INPUT ;
    USE SIGNAL ;
    ANTENNAGATEAREA 0.213000 ;
    PORT
      LAYER met2 ;
        RECT 397.070 0.000 397.350 4.000 ;
    END
  END sstreams_i[87]
  PIN sstreams_i[88]
    DIRECTION INPUT ;
    USE SIGNAL ;
    ANTENNAGATEAREA 0.213000 ;
    PORT
      LAYER met2 ;
        RECT 401.210 0.000 401.490 4.000 ;
    END
  END sstreams_i[88]
  PIN sstreams_i[89]
    DIRECTION INPUT ;
    USE SIGNAL ;
    ANTENNAGATEAREA 0.213000 ;
    PORT
      LAYER met2 ;
        RECT 405.350 0.000 405.630 4.000 ;
    END
  END sstreams_i[89]
  PIN sstreams_i[8]
    DIRECTION INPUT ;
    USE SIGNAL ;
    ANTENNAGATEAREA 0.196500 ;
    PORT
      LAYER met2 ;
        RECT 70.010 0.000 70.290 4.000 ;
    END
  END sstreams_i[8]
  PIN sstreams_i[90]
    DIRECTION INPUT ;
    USE SIGNAL ;
    ANTENNAGATEAREA 0.213000 ;
    PORT
      LAYER met2 ;
        RECT 409.490 0.000 409.770 4.000 ;
    END
  END sstreams_i[90]
  PIN sstreams_i[91]
    DIRECTION INPUT ;
    USE SIGNAL ;
    ANTENNAGATEAREA 0.213000 ;
    PORT
      LAYER met2 ;
        RECT 413.630 0.000 413.910 4.000 ;
    END
  END sstreams_i[91]
  PIN sstreams_i[92]
    DIRECTION INPUT ;
    USE SIGNAL ;
    ANTENNAGATEAREA 0.213000 ;
    PORT
      LAYER met2 ;
        RECT 417.770 0.000 418.050 4.000 ;
    END
  END sstreams_i[92]
  PIN sstreams_i[93]
    DIRECTION INPUT ;
    USE SIGNAL ;
    ANTENNAGATEAREA 0.213000 ;
    PORT
      LAYER met2 ;
        RECT 421.910 0.000 422.190 4.000 ;
    END
  END sstreams_i[93]
  PIN sstreams_i[94]
    DIRECTION INPUT ;
    USE SIGNAL ;
    ANTENNAGATEAREA 0.213000 ;
    PORT
      LAYER met2 ;
        RECT 426.050 0.000 426.330 4.000 ;
    END
  END sstreams_i[94]
  PIN sstreams_i[95]
    DIRECTION INPUT ;
    USE SIGNAL ;
    ANTENNAGATEAREA 0.213000 ;
    PORT
      LAYER met2 ;
        RECT 430.190 0.000 430.470 4.000 ;
    END
  END sstreams_i[95]
  PIN sstreams_i[96]
    DIRECTION INPUT ;
    USE SIGNAL ;
    ANTENNAGATEAREA 0.495000 ;
    PORT
      LAYER met2 ;
        RECT 434.330 0.000 434.610 4.000 ;
    END
  END sstreams_i[96]
  PIN sstreams_i[97]
    DIRECTION INPUT ;
    USE SIGNAL ;
    PORT
      LAYER met2 ;
        RECT 438.470 0.000 438.750 4.000 ;
    END
  END sstreams_i[97]
  PIN sstreams_i[98]
    DIRECTION INPUT ;
    USE SIGNAL ;
    ANTENNAGATEAREA 0.196500 ;
    PORT
      LAYER met2 ;
        RECT 442.610 0.000 442.890 4.000 ;
    END
  END sstreams_i[98]
  PIN sstreams_i[99]
    DIRECTION INPUT ;
    USE SIGNAL ;
    ANTENNAGATEAREA 0.196500 ;
    PORT
      LAYER met2 ;
        RECT 446.750 0.000 447.030 4.000 ;
    END
  END sstreams_i[99]
  PIN sstreams_i[9]
    DIRECTION INPUT ;
    USE SIGNAL ;
    ANTENNAGATEAREA 0.196500 ;
    PORT
      LAYER met2 ;
        RECT 74.150 0.000 74.430 4.000 ;
    END
  END sstreams_i[9]
  PIN sstreams_o[0]
    DIRECTION OUTPUT TRISTATE ;
    USE SIGNAL ;
    ANTENNADIFFAREA 2.673000 ;
    PORT
      LAYER met2 ;
        RECT 1254.050 0.000 1254.330 4.000 ;
    END
  END sstreams_o[0]
  PIN sstreams_o[1]
    DIRECTION OUTPUT TRISTATE ;
    USE SIGNAL ;
    ANTENNADIFFAREA 2.673000 ;
    PORT
      LAYER met2 ;
        RECT 1258.190 0.000 1258.470 4.000 ;
    END
  END sstreams_o[1]
  PIN sstreams_o[2]
    DIRECTION OUTPUT TRISTATE ;
    USE SIGNAL ;
    ANTENNADIFFAREA 2.673000 ;
    PORT
      LAYER met2 ;
        RECT 1262.330 0.000 1262.610 4.000 ;
    END
  END sstreams_o[2]
  PIN vccd1
    DIRECTION INOUT ;
    USE POWER ;
    PORT
      LAYER met4 ;
        RECT 21.040 10.640 22.640 389.200 ;
    END
    PORT
      LAYER met4 ;
        RECT 174.640 10.640 176.240 389.200 ;
    END
    PORT
      LAYER met4 ;
        RECT 328.240 10.640 329.840 389.200 ;
    END
    PORT
      LAYER met4 ;
        RECT 481.840 10.640 483.440 389.200 ;
    END
    PORT
      LAYER met4 ;
        RECT 635.440 10.640 637.040 389.200 ;
    END
    PORT
      LAYER met4 ;
        RECT 789.040 10.640 790.640 389.200 ;
    END
    PORT
      LAYER met4 ;
        RECT 942.640 10.640 944.240 389.200 ;
    END
    PORT
      LAYER met4 ;
        RECT 1096.240 10.640 1097.840 389.200 ;
    END
    PORT
      LAYER met4 ;
        RECT 1249.840 10.640 1251.440 389.200 ;
    END
  END vccd1
  PIN vssd1
    DIRECTION INOUT ;
    USE GROUND ;
    PORT
      LAYER met4 ;
        RECT 97.840 10.640 99.440 389.200 ;
    END
    PORT
      LAYER met4 ;
        RECT 251.440 10.640 253.040 389.200 ;
    END
    PORT
      LAYER met4 ;
        RECT 405.040 10.640 406.640 389.200 ;
    END
    PORT
      LAYER met4 ;
        RECT 558.640 10.640 560.240 389.200 ;
    END
    PORT
      LAYER met4 ;
        RECT 712.240 10.640 713.840 389.200 ;
    END
    PORT
      LAYER met4 ;
        RECT 865.840 10.640 867.440 389.200 ;
    END
    PORT
      LAYER met4 ;
        RECT 1019.440 10.640 1021.040 389.200 ;
    END
    PORT
      LAYER met4 ;
        RECT 1173.040 10.640 1174.640 389.200 ;
    END
  END vssd1
  OBS
      LAYER li1 ;
        RECT 5.520 10.795 1294.440 389.045 ;
      LAYER met1 ;
        RECT 4.670 0.040 1297.590 390.620 ;
      LAYER met2 ;
        RECT 4.690 4.280 1297.560 390.650 ;
        RECT 4.690 0.010 36.610 4.280 ;
        RECT 37.450 0.010 40.750 4.280 ;
        RECT 41.590 0.010 44.890 4.280 ;
        RECT 45.730 0.010 49.030 4.280 ;
        RECT 49.870 0.010 53.170 4.280 ;
        RECT 54.010 0.010 57.310 4.280 ;
        RECT 58.150 0.010 61.450 4.280 ;
        RECT 62.290 0.010 65.590 4.280 ;
        RECT 66.430 0.010 69.730 4.280 ;
        RECT 70.570 0.010 73.870 4.280 ;
        RECT 74.710 0.010 78.010 4.280 ;
        RECT 78.850 0.010 82.150 4.280 ;
        RECT 82.990 0.010 86.290 4.280 ;
        RECT 87.130 0.010 90.430 4.280 ;
        RECT 91.270 0.010 94.570 4.280 ;
        RECT 95.410 0.010 98.710 4.280 ;
        RECT 99.550 0.010 102.850 4.280 ;
        RECT 103.690 0.010 106.990 4.280 ;
        RECT 107.830 0.010 111.130 4.280 ;
        RECT 111.970 0.010 115.270 4.280 ;
        RECT 116.110 0.010 119.410 4.280 ;
        RECT 120.250 0.010 123.550 4.280 ;
        RECT 124.390 0.010 127.690 4.280 ;
        RECT 128.530 0.010 131.830 4.280 ;
        RECT 132.670 0.010 135.970 4.280 ;
        RECT 136.810 0.010 140.110 4.280 ;
        RECT 140.950 0.010 144.250 4.280 ;
        RECT 145.090 0.010 148.390 4.280 ;
        RECT 149.230 0.010 152.530 4.280 ;
        RECT 153.370 0.010 156.670 4.280 ;
        RECT 157.510 0.010 160.810 4.280 ;
        RECT 161.650 0.010 164.950 4.280 ;
        RECT 165.790 0.010 169.090 4.280 ;
        RECT 169.930 0.010 173.230 4.280 ;
        RECT 174.070 0.010 177.370 4.280 ;
        RECT 178.210 0.010 181.510 4.280 ;
        RECT 182.350 0.010 185.650 4.280 ;
        RECT 186.490 0.010 189.790 4.280 ;
        RECT 190.630 0.010 193.930 4.280 ;
        RECT 194.770 0.010 198.070 4.280 ;
        RECT 198.910 0.010 202.210 4.280 ;
        RECT 203.050 0.010 206.350 4.280 ;
        RECT 207.190 0.010 210.490 4.280 ;
        RECT 211.330 0.010 214.630 4.280 ;
        RECT 215.470 0.010 218.770 4.280 ;
        RECT 219.610 0.010 222.910 4.280 ;
        RECT 223.750 0.010 227.050 4.280 ;
        RECT 227.890 0.010 231.190 4.280 ;
        RECT 232.030 0.010 235.330 4.280 ;
        RECT 236.170 0.010 239.470 4.280 ;
        RECT 240.310 0.010 243.610 4.280 ;
        RECT 244.450 0.010 247.750 4.280 ;
        RECT 248.590 0.010 251.890 4.280 ;
        RECT 252.730 0.010 256.030 4.280 ;
        RECT 256.870 0.010 260.170 4.280 ;
        RECT 261.010 0.010 264.310 4.280 ;
        RECT 265.150 0.010 268.450 4.280 ;
        RECT 269.290 0.010 272.590 4.280 ;
        RECT 273.430 0.010 276.730 4.280 ;
        RECT 277.570 0.010 280.870 4.280 ;
        RECT 281.710 0.010 285.010 4.280 ;
        RECT 285.850 0.010 289.150 4.280 ;
        RECT 289.990 0.010 293.290 4.280 ;
        RECT 294.130 0.010 297.430 4.280 ;
        RECT 298.270 0.010 301.570 4.280 ;
        RECT 302.410 0.010 305.710 4.280 ;
        RECT 306.550 0.010 309.850 4.280 ;
        RECT 310.690 0.010 313.990 4.280 ;
        RECT 314.830 0.010 318.130 4.280 ;
        RECT 318.970 0.010 322.270 4.280 ;
        RECT 323.110 0.010 326.410 4.280 ;
        RECT 327.250 0.010 330.550 4.280 ;
        RECT 331.390 0.010 334.690 4.280 ;
        RECT 335.530 0.010 338.830 4.280 ;
        RECT 339.670 0.010 342.970 4.280 ;
        RECT 343.810 0.010 347.110 4.280 ;
        RECT 347.950 0.010 351.250 4.280 ;
        RECT 352.090 0.010 355.390 4.280 ;
        RECT 356.230 0.010 359.530 4.280 ;
        RECT 360.370 0.010 363.670 4.280 ;
        RECT 364.510 0.010 367.810 4.280 ;
        RECT 368.650 0.010 371.950 4.280 ;
        RECT 372.790 0.010 376.090 4.280 ;
        RECT 376.930 0.010 380.230 4.280 ;
        RECT 381.070 0.010 384.370 4.280 ;
        RECT 385.210 0.010 388.510 4.280 ;
        RECT 389.350 0.010 392.650 4.280 ;
        RECT 393.490 0.010 396.790 4.280 ;
        RECT 397.630 0.010 400.930 4.280 ;
        RECT 401.770 0.010 405.070 4.280 ;
        RECT 405.910 0.010 409.210 4.280 ;
        RECT 410.050 0.010 413.350 4.280 ;
        RECT 414.190 0.010 417.490 4.280 ;
        RECT 418.330 0.010 421.630 4.280 ;
        RECT 422.470 0.010 425.770 4.280 ;
        RECT 426.610 0.010 429.910 4.280 ;
        RECT 430.750 0.010 434.050 4.280 ;
        RECT 434.890 0.010 438.190 4.280 ;
        RECT 439.030 0.010 442.330 4.280 ;
        RECT 443.170 0.010 446.470 4.280 ;
        RECT 447.310 0.010 450.610 4.280 ;
        RECT 451.450 0.010 454.750 4.280 ;
        RECT 455.590 0.010 458.890 4.280 ;
        RECT 459.730 0.010 463.030 4.280 ;
        RECT 463.870 0.010 467.170 4.280 ;
        RECT 468.010 0.010 471.310 4.280 ;
        RECT 472.150 0.010 475.450 4.280 ;
        RECT 476.290 0.010 479.590 4.280 ;
        RECT 480.430 0.010 483.730 4.280 ;
        RECT 484.570 0.010 487.870 4.280 ;
        RECT 488.710 0.010 492.010 4.280 ;
        RECT 492.850 0.010 496.150 4.280 ;
        RECT 496.990 0.010 500.290 4.280 ;
        RECT 501.130 0.010 504.430 4.280 ;
        RECT 505.270 0.010 508.570 4.280 ;
        RECT 509.410 0.010 512.710 4.280 ;
        RECT 513.550 0.010 516.850 4.280 ;
        RECT 517.690 0.010 520.990 4.280 ;
        RECT 521.830 0.010 525.130 4.280 ;
        RECT 525.970 0.010 529.270 4.280 ;
        RECT 530.110 0.010 533.410 4.280 ;
        RECT 534.250 0.010 537.550 4.280 ;
        RECT 538.390 0.010 541.690 4.280 ;
        RECT 542.530 0.010 545.830 4.280 ;
        RECT 546.670 0.010 549.970 4.280 ;
        RECT 550.810 0.010 554.110 4.280 ;
        RECT 554.950 0.010 558.250 4.280 ;
        RECT 559.090 0.010 562.390 4.280 ;
        RECT 563.230 0.010 566.530 4.280 ;
        RECT 567.370 0.010 570.670 4.280 ;
        RECT 571.510 0.010 574.810 4.280 ;
        RECT 575.650 0.010 578.950 4.280 ;
        RECT 579.790 0.010 583.090 4.280 ;
        RECT 583.930 0.010 587.230 4.280 ;
        RECT 588.070 0.010 591.370 4.280 ;
        RECT 592.210 0.010 595.510 4.280 ;
        RECT 596.350 0.010 599.650 4.280 ;
        RECT 600.490 0.010 603.790 4.280 ;
        RECT 604.630 0.010 607.930 4.280 ;
        RECT 608.770 0.010 612.070 4.280 ;
        RECT 612.910 0.010 616.210 4.280 ;
        RECT 617.050 0.010 620.350 4.280 ;
        RECT 621.190 0.010 624.490 4.280 ;
        RECT 625.330 0.010 628.630 4.280 ;
        RECT 629.470 0.010 632.770 4.280 ;
        RECT 633.610 0.010 636.910 4.280 ;
        RECT 637.750 0.010 641.050 4.280 ;
        RECT 641.890 0.010 645.190 4.280 ;
        RECT 646.030 0.010 649.330 4.280 ;
        RECT 650.170 0.010 653.470 4.280 ;
        RECT 654.310 0.010 657.610 4.280 ;
        RECT 658.450 0.010 661.750 4.280 ;
        RECT 662.590 0.010 665.890 4.280 ;
        RECT 666.730 0.010 670.030 4.280 ;
        RECT 670.870 0.010 674.170 4.280 ;
        RECT 675.010 0.010 678.310 4.280 ;
        RECT 679.150 0.010 682.450 4.280 ;
        RECT 683.290 0.010 686.590 4.280 ;
        RECT 687.430 0.010 690.730 4.280 ;
        RECT 691.570 0.010 694.870 4.280 ;
        RECT 695.710 0.010 699.010 4.280 ;
        RECT 699.850 0.010 703.150 4.280 ;
        RECT 703.990 0.010 707.290 4.280 ;
        RECT 708.130 0.010 711.430 4.280 ;
        RECT 712.270 0.010 715.570 4.280 ;
        RECT 716.410 0.010 719.710 4.280 ;
        RECT 720.550 0.010 723.850 4.280 ;
        RECT 724.690 0.010 727.990 4.280 ;
        RECT 728.830 0.010 732.130 4.280 ;
        RECT 732.970 0.010 736.270 4.280 ;
        RECT 737.110 0.010 740.410 4.280 ;
        RECT 741.250 0.010 744.550 4.280 ;
        RECT 745.390 0.010 748.690 4.280 ;
        RECT 749.530 0.010 752.830 4.280 ;
        RECT 753.670 0.010 756.970 4.280 ;
        RECT 757.810 0.010 761.110 4.280 ;
        RECT 761.950 0.010 765.250 4.280 ;
        RECT 766.090 0.010 769.390 4.280 ;
        RECT 770.230 0.010 773.530 4.280 ;
        RECT 774.370 0.010 777.670 4.280 ;
        RECT 778.510 0.010 781.810 4.280 ;
        RECT 782.650 0.010 785.950 4.280 ;
        RECT 786.790 0.010 790.090 4.280 ;
        RECT 790.930 0.010 794.230 4.280 ;
        RECT 795.070 0.010 798.370 4.280 ;
        RECT 799.210 0.010 802.510 4.280 ;
        RECT 803.350 0.010 806.650 4.280 ;
        RECT 807.490 0.010 810.790 4.280 ;
        RECT 811.630 0.010 814.930 4.280 ;
        RECT 815.770 0.010 819.070 4.280 ;
        RECT 819.910 0.010 823.210 4.280 ;
        RECT 824.050 0.010 827.350 4.280 ;
        RECT 828.190 0.010 831.490 4.280 ;
        RECT 832.330 0.010 835.630 4.280 ;
        RECT 836.470 0.010 839.770 4.280 ;
        RECT 840.610 0.010 843.910 4.280 ;
        RECT 844.750 0.010 848.050 4.280 ;
        RECT 848.890 0.010 852.190 4.280 ;
        RECT 853.030 0.010 856.330 4.280 ;
        RECT 857.170 0.010 860.470 4.280 ;
        RECT 861.310 0.010 864.610 4.280 ;
        RECT 865.450 0.010 868.750 4.280 ;
        RECT 869.590 0.010 872.890 4.280 ;
        RECT 873.730 0.010 877.030 4.280 ;
        RECT 877.870 0.010 881.170 4.280 ;
        RECT 882.010 0.010 885.310 4.280 ;
        RECT 886.150 0.010 889.450 4.280 ;
        RECT 890.290 0.010 893.590 4.280 ;
        RECT 894.430 0.010 897.730 4.280 ;
        RECT 898.570 0.010 901.870 4.280 ;
        RECT 902.710 0.010 906.010 4.280 ;
        RECT 906.850 0.010 910.150 4.280 ;
        RECT 910.990 0.010 914.290 4.280 ;
        RECT 915.130 0.010 918.430 4.280 ;
        RECT 919.270 0.010 922.570 4.280 ;
        RECT 923.410 0.010 926.710 4.280 ;
        RECT 927.550 0.010 930.850 4.280 ;
        RECT 931.690 0.010 934.990 4.280 ;
        RECT 935.830 0.010 939.130 4.280 ;
        RECT 939.970 0.010 943.270 4.280 ;
        RECT 944.110 0.010 947.410 4.280 ;
        RECT 948.250 0.010 951.550 4.280 ;
        RECT 952.390 0.010 955.690 4.280 ;
        RECT 956.530 0.010 959.830 4.280 ;
        RECT 960.670 0.010 963.970 4.280 ;
        RECT 964.810 0.010 968.110 4.280 ;
        RECT 968.950 0.010 972.250 4.280 ;
        RECT 973.090 0.010 976.390 4.280 ;
        RECT 977.230 0.010 980.530 4.280 ;
        RECT 981.370 0.010 984.670 4.280 ;
        RECT 985.510 0.010 988.810 4.280 ;
        RECT 989.650 0.010 992.950 4.280 ;
        RECT 993.790 0.010 997.090 4.280 ;
        RECT 997.930 0.010 1001.230 4.280 ;
        RECT 1002.070 0.010 1005.370 4.280 ;
        RECT 1006.210 0.010 1009.510 4.280 ;
        RECT 1010.350 0.010 1013.650 4.280 ;
        RECT 1014.490 0.010 1017.790 4.280 ;
        RECT 1018.630 0.010 1021.930 4.280 ;
        RECT 1022.770 0.010 1026.070 4.280 ;
        RECT 1026.910 0.010 1030.210 4.280 ;
        RECT 1031.050 0.010 1034.350 4.280 ;
        RECT 1035.190 0.010 1038.490 4.280 ;
        RECT 1039.330 0.010 1042.630 4.280 ;
        RECT 1043.470 0.010 1046.770 4.280 ;
        RECT 1047.610 0.010 1050.910 4.280 ;
        RECT 1051.750 0.010 1055.050 4.280 ;
        RECT 1055.890 0.010 1059.190 4.280 ;
        RECT 1060.030 0.010 1063.330 4.280 ;
        RECT 1064.170 0.010 1067.470 4.280 ;
        RECT 1068.310 0.010 1071.610 4.280 ;
        RECT 1072.450 0.010 1075.750 4.280 ;
        RECT 1076.590 0.010 1079.890 4.280 ;
        RECT 1080.730 0.010 1084.030 4.280 ;
        RECT 1084.870 0.010 1088.170 4.280 ;
        RECT 1089.010 0.010 1092.310 4.280 ;
        RECT 1093.150 0.010 1096.450 4.280 ;
        RECT 1097.290 0.010 1100.590 4.280 ;
        RECT 1101.430 0.010 1104.730 4.280 ;
        RECT 1105.570 0.010 1108.870 4.280 ;
        RECT 1109.710 0.010 1113.010 4.280 ;
        RECT 1113.850 0.010 1117.150 4.280 ;
        RECT 1117.990 0.010 1121.290 4.280 ;
        RECT 1122.130 0.010 1125.430 4.280 ;
        RECT 1126.270 0.010 1129.570 4.280 ;
        RECT 1130.410 0.010 1133.710 4.280 ;
        RECT 1134.550 0.010 1137.850 4.280 ;
        RECT 1138.690 0.010 1141.990 4.280 ;
        RECT 1142.830 0.010 1146.130 4.280 ;
        RECT 1146.970 0.010 1150.270 4.280 ;
        RECT 1151.110 0.010 1154.410 4.280 ;
        RECT 1155.250 0.010 1158.550 4.280 ;
        RECT 1159.390 0.010 1162.690 4.280 ;
        RECT 1163.530 0.010 1166.830 4.280 ;
        RECT 1167.670 0.010 1170.970 4.280 ;
        RECT 1171.810 0.010 1175.110 4.280 ;
        RECT 1175.950 0.010 1179.250 4.280 ;
        RECT 1180.090 0.010 1183.390 4.280 ;
        RECT 1184.230 0.010 1187.530 4.280 ;
        RECT 1188.370 0.010 1191.670 4.280 ;
        RECT 1192.510 0.010 1195.810 4.280 ;
        RECT 1196.650 0.010 1199.950 4.280 ;
        RECT 1200.790 0.010 1204.090 4.280 ;
        RECT 1204.930 0.010 1208.230 4.280 ;
        RECT 1209.070 0.010 1212.370 4.280 ;
        RECT 1213.210 0.010 1216.510 4.280 ;
        RECT 1217.350 0.010 1220.650 4.280 ;
        RECT 1221.490 0.010 1224.790 4.280 ;
        RECT 1225.630 0.010 1228.930 4.280 ;
        RECT 1229.770 0.010 1233.070 4.280 ;
        RECT 1233.910 0.010 1237.210 4.280 ;
        RECT 1238.050 0.010 1241.350 4.280 ;
        RECT 1242.190 0.010 1245.490 4.280 ;
        RECT 1246.330 0.010 1249.630 4.280 ;
        RECT 1250.470 0.010 1253.770 4.280 ;
        RECT 1254.610 0.010 1257.910 4.280 ;
        RECT 1258.750 0.010 1262.050 4.280 ;
        RECT 1262.890 0.010 1297.560 4.280 ;
      LAYER met3 ;
        RECT 4.000 302.960 1296.675 389.125 ;
        RECT 4.000 300.240 1295.600 302.960 ;
        RECT 4.400 298.840 1295.600 300.240 ;
        RECT 4.000 100.320 1295.600 298.840 ;
        RECT 4.400 98.920 1295.600 100.320 ;
        RECT 4.000 94.840 1295.600 98.920 ;
        RECT 4.000 0.175 1296.675 94.840 ;
      LAYER met4 ;
        RECT 16.855 10.240 20.640 386.745 ;
        RECT 23.040 10.240 97.440 386.745 ;
        RECT 99.840 10.240 174.240 386.745 ;
        RECT 176.640 10.240 251.040 386.745 ;
        RECT 253.440 10.240 327.840 386.745 ;
        RECT 330.240 10.240 404.640 386.745 ;
        RECT 407.040 10.240 481.440 386.745 ;
        RECT 483.840 10.240 558.240 386.745 ;
        RECT 560.640 10.240 635.040 386.745 ;
        RECT 637.440 10.240 711.840 386.745 ;
        RECT 714.240 10.240 788.640 386.745 ;
        RECT 791.040 10.240 865.440 386.745 ;
        RECT 867.840 10.240 942.240 386.745 ;
        RECT 944.640 10.240 1019.040 386.745 ;
        RECT 1021.440 10.240 1095.840 386.745 ;
        RECT 1098.240 10.240 1172.640 386.745 ;
        RECT 1175.040 10.240 1249.440 386.745 ;
        RECT 1251.840 10.240 1288.625 386.745 ;
        RECT 16.855 1.535 1288.625 10.240 ;
  END
END shared_div_rasterizer_m
END LIBRARY

